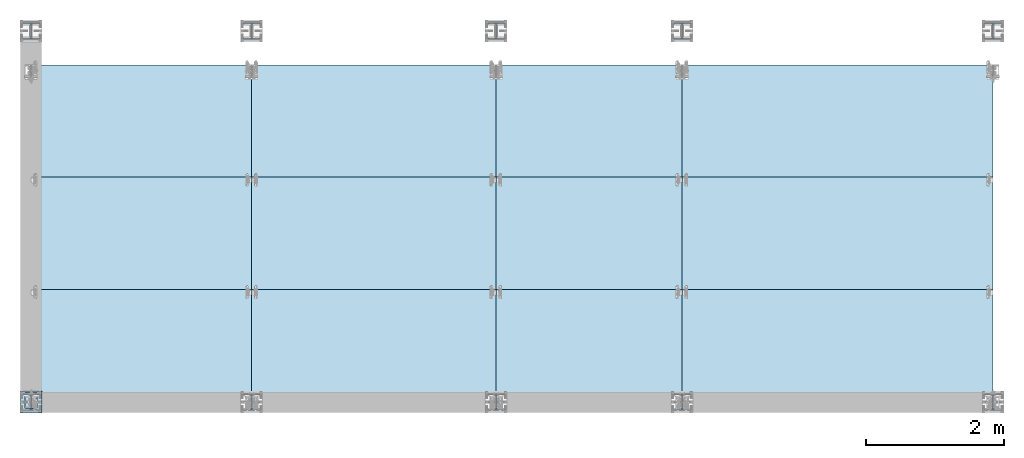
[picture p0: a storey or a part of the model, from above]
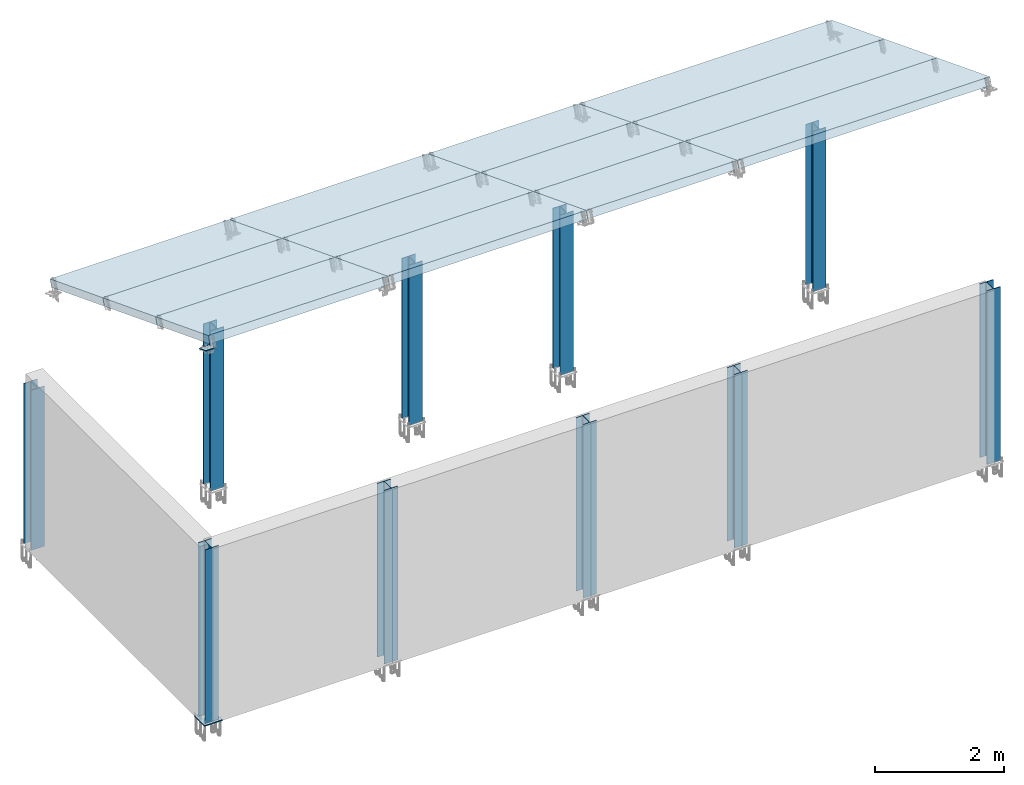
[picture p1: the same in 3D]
Properties of the parts of a building model (IFC4), part 1 of 2

# File
Description: ViewDefinition [CoordinationView]
Made in: IFC file generated by ModeSt (Tecnisoft s.a.s.)

# IfcBuildingStorey (2)
In: Uffici
Name | Elevation (m)
Storey 0 | 0
Storey 1 | 3.3

# IfcBeam: 2 HEB240 (25)
In: Storey 1
Type - PredefinedType: BEAM; Material: Acciaio
Description: 2 HEB240 - Acciaio
Pset_BeamCommon - LoadBearing: yes
BaseQuantities - ?: 0.01022 m2
Name | BaseQuantities, ? (m3) | BaseQuantities, ? (m)
108 | 0.0183619 | 1.79667
2 x 108 | 0.00918097 | 0.898333
108 | 0.0133541 | 1.30667
111 | 0.0183619 | 1.79667
2 x 111 | 0.00918097 | 0.898333
111 | 0.0133541 | 1.30667
110 | 0.0183619 | 1.79667
2 x 110 | 0.00918097 | 0.898333
110 | 0.0133541 | 1.30667
109 | 0.0183619 | 1.79667
2 x 109 | 0.00918097 | 0.898333
109 | 0.0133541 | 1.30667
112 | 0.0183619 | 1.79667
112 | 0.0050078 | 0.49
109 | 0.0050078 | 0.49
110 | 0.0050078 | 0.49
111 | 0.0050078 | 0.49
108 | 0.0050078 | 0.49
2 x 112 | 0.00918097 | 0.898333
112 | 0.0133541 | 1.30667

# IfcBeam: 3 IPE240 (16)
In: Storey 1
Type - PredefinedType: BEAM; Material: Acciaio
Description: 3 IPE240 - Acciaio
Pset_BeamCommon - LoadBearing: yes
BaseQuantities - ?: 0.00371848 m2
Name | BaseQuantities, ? (m3) | BaseQuantities, ? (m)
101 | 0.0100399 | 2.7
101 | 0.0132006 | 3.55
101 | 0.0119177 | 3.205
103 | 0.0100399 | 2.7
103 | 0.0132006 | 3.55
103 | 0.0119177 | 3.205
101 | 0.0167889 | 4.515
105 | 0.0100399 | 2.7
105 | 0.0132006 | 3.55
105 | 0.0119177 | 3.205
107 | 0.0100399 | 2.7
107 | 0.0132006 | 3.55
107 | 0.0119177 | 3.205
103 | 0.0167889 | 4.515
105 | 0.0167889 | 4.515
107 | 0.0167889 | 4.515

# IfcBeam: 5 IPE220 (20)
In: Storey 1
Type - PredefinedType: BEAM; Material: Acciaio
Description: 5 IPE220 - Acciaio
Pset_BeamCommon - LoadBearing: yes
BaseQuantities - ?: 0.00321344 m2
Name | BaseQuantities, ? (m3) | BaseQuantities, ? (m)
2 x 208 | 0.00281469 | 0.875912
2 x 209 | 0.00281469 | 0.875912
2 x 210 | 0.00281469 | 0.875912
2 x 212 | 0.00562938 | 1.75182
2 x 212 | 0.00281469 | 0.875912
2 x 211 | 0.00562938 | 1.75182
2 x 211 | 0.00281469 | 0.875912
2 x 210 | 0.00562938 | 1.75182
2 x 209 | 0.00562938 | 1.75182
2 x 208 | 0.00562938 | 1.75182

# IfcBeam: 6 IPE200 (16)
In: Storey 1
Type - PredefinedType: BEAM; Material: Acciaio
Description: 6 IPE200 - Acciaio
Pset_BeamCommon - LoadBearing: yes
BaseQuantities - ?: 0.0027248 m2
Name | BaseQuantities, ? (m3) | BaseQuantities, ? (m)
230 | 0.0123025 | 4.515
230 | 0.00735696 | 2.7
230 | 0.00967304 | 3.55
230 | 0.00873298 | 3.205
204 | 0.0123025 | 4.515
204 | 0.00735696 | 2.7
204 | 0.00967304 | 3.55
204 | 0.00873298 | 3.205
202 | 0.0123025 | 4.515
202 | 0.00735696 | 2.7
202 | 0.00967304 | 3.55
202 | 0.00873298 | 3.205
201 | 0.0123025 | 4.515
201 | 0.00735696 | 2.7
201 | 0.00967304 | 3.55
201 | 0.00873298 | 3.205

# IfcBuildingElementProxy: 4 Piatto50x5 (12)
In: Storey 1
Type - PredefinedType: MEMBER; Material: Acciaio controventi
Description: 4 Piatto50x5 - Acciaio
Pset_MemberCommon - LoadBearing: yes
BaseQuantities - ?: 0.00025 m2
Name | BaseQuantities, ? (m3) | BaseQuantities, ? (m)
2 x 0 | 0.00157189 | 6.28758
2 x 0 | 0.00123862 | 4.95447
2 x 0 | 0.00094979 | 3.79916
2 x 0 | 0.00132692 | 5.30769
2 x 0 | 0.00126973 | 5.07894
2 x 0 | 0.0014981 | 5.9924

# IfcColumn: 1 HEA240 (10)
In: Storey 0
Type - PredefinedType: COLUMN; Material: Acciaio
Description: 1 HEA240 - Acciaio
Pset_ColumnCommon - LoadBearing: yes
BaseQuantities - ?: 0.007305 m2; ?: 0.0241065 m3; ?: 3.3 m
Name
1
11
4
14
3
13
2
12
15
5

# IfcColumn: 7 HEA180 (10)
In: Storey 1
Type - PredefinedType: COLUMN; Material: Acciaio
Description: 7 HEA180 - Acciaio
Pset_ColumnCommon - LoadBearing: yes
BaseQuantities - ?: 0.004332 m2
Name | BaseQuantities, ? (m3) | BaseQuantities, ? (m)
10 | 0.00883728 | 2.04
9 | 0.00883728 | 2.04
8 | 0.00883728 | 2.04
7 | 0.00883728 | 2.04
6 | 0.00883728 | 2.04
5 | 0.0170681 | 3.94
4 | 0.0170681 | 3.94
3 | 0.0170681 | 3.94
2 | 0.0170681 | 3.94
1 | 0.0170681 | 3.94

# IfcFastener: Collegamenti -005_-004 -015_-014 0115_0114 (42)
In: Storey 1
Type - PredefinedType: WELD
Name | Description
36 x Collegamenti -005_-004 -015_-014 0115_0114 | 8x8
6 x Collegamenti -005_-004 -015_-014 0115_0114 | 15x15

# IfcFastener: Collegamenti 0001_0101 0002_0102 0003_0103 0004_0104 0005_0105 0011_0111 0012_0112 0013_0113 0014_0114 0015_0115 (160)
In: Storey 0
Type - PredefinedType: WELD
Description: 10x10

# IfcFastener: Collegamenti 0101_-001 0102_-002 0103_-003 0104_-004 (56)
In: Storey 1
Type - PredefinedType: WELD
Description: 14x14

# IfcFastener: Collegamenti 0101_0201 0102_0202 0103_0203 0104_0204 0105_0205 (120)
In: Storey 1
Type - PredefinedType: WELD
Name | Description
60 x Collegamenti 0101_0201 0102_0202 0103_0203 0104_0204 0105_0205 | 13x13
20 x Collegamenti 0101_0201 0102_0202 0103_0203 0104_0204 0105_0205 | 8x8
30 x Collegamenti 0101_0201 0102_0202 0103_0203 0104_0204 0105_0205 | 15x15
10 x Collegamenti 0101_0201 0102_0202 0103_0203 0104_0204 0105_0205 | 10x10

# IfcFastener: Collegamenti 0111_0011 0112_0012 0113_0013 0114_0014 0115_0015 (70)
In: Storey 1
Type - PredefinedType: WELD
Description: 10x10

# IfcFastener: Collegamento -001_-002 (14)
In: Storey 1
Type - PredefinedType: WELD
Name | Description
12 x Collegamento -001_-002 | 8x8
2 x Collegamento -001_-002 | 10x10

# IfcFastener: Collegamento -002_-001 (14)
In: Storey 1
Type - PredefinedType: WELD
Name | Description
12 x Collegamento -002_-001 | 8x8
2 x Collegamento -002_-001 | 10x10

# IfcFastener: Collegamento -002_-003 (14)
In: Storey 1
Type - PredefinedType: WELD
Name | Description
12 x Collegamento -002_-003 | 8x8
2 x Collegamento -002_-003 | 10x10

# IfcFastener: Collegamento -003_-002 (14)
In: Storey 1
Type - PredefinedType: WELD
Name | Description
12 x Collegamento -003_-002 | 8x8
2 x Collegamento -003_-002 | 10x10

# IfcFastener: Collegamento -003_-004 (14)
In: Storey 1
Type - PredefinedType: WELD
Name | Description
12 x Collegamento -003_-004 | 8x8
2 x Collegamento -003_-004 | 10x10

# IfcFastener: Collegamento -004_-003 (14)
In: Storey 1
Type - PredefinedType: WELD
Name | Description
12 x Collegamento -004_-003 | 8x8
2 x Collegamento -004_-003 | 10x10

# IfcFastener: Collegamento -004_-005 (14)
In: Storey 1
Type - PredefinedType: WELD
Name | Description
12 x Collegamento -004_-005 | 8x8
2 x Collegamento -004_-005 | 15x15

# IfcFastener: Collegamento -011_-012 (14)
In: Storey 1
Type - PredefinedType: WELD
Name | Description
12 x Collegamento -011_-012 | 8x8
2 x Collegamento -011_-012 | 10x10

# IfcFastener: Collegamento -012_-011 (14)
In: Storey 1
Type - PredefinedType: WELD
Name | Description
12 x Collegamento -012_-011 | 8x8
2 x Collegamento -012_-011 | 10x10

# IfcFastener: Collegamento -012_-013 (14)
In: Storey 1
Type - PredefinedType: WELD
Name | Description
12 x Collegamento -012_-013 | 8x8
2 x Collegamento -012_-013 | 10x10

# IfcFastener: Collegamento -013_-012 (14)
In: Storey 1
Type - PredefinedType: WELD
Name | Description
12 x Collegamento -013_-012 | 8x8
2 x Collegamento -013_-012 | 10x10

# IfcFastener: Collegamento -013_-014 (14)
In: Storey 1
Type - PredefinedType: WELD
Name | Description
12 x Collegamento -013_-014 | 8x8
2 x Collegamento -013_-014 | 10x10

# IfcFastener: Collegamento -014_-013 (14)
In: Storey 1
Type - PredefinedType: WELD
Name | Description
12 x Collegamento -014_-013 | 8x8
2 x Collegamento -014_-013 | 10x10

# IfcFastener: Collegamento -014_-015 (14)
In: Storey 1
Type - PredefinedType: WELD
Name | Description
12 x Collegamento -014_-015 | 8x8
2 x Collegamento -014_-015 | 15x15

# IfcFastener: Collegamento -016_-017 (16)
In: Storey 0
Type - PredefinedType: WELD
Name | Description
14 x Collegamento -016_-017 | 7x7
2 x Collegamento -016_-017 | 9x9

# IfcFastener: Collegamento -017_-016 (16)
In: Storey 0
Type - PredefinedType: WELD
Name | Description
14 x Collegamento -017_-016 | 7x7
2 x Collegamento -017_-016 | 9x9

# IfcFastener: Collegamento -017_-018 (16)
In: Storey 0
Type - PredefinedType: WELD
Name | Description
14 x Collegamento -017_-018 | 7x7
2 x Collegamento -017_-018 | 9x9

# IfcFastener: Collegamento -018_-017 (16)
In: Storey 0
Type - PredefinedType: WELD
Name | Description
14 x Collegamento -018_-017 | 7x7
2 x Collegamento -018_-017 | 9x9

# IfcFastener: Collegamento -018_-019 (16)
In: Storey 0
Type - PredefinedType: WELD
Name | Description
14 x Collegamento -018_-019 | 7x7
2 x Collegamento -018_-019 | 9x9

# IfcFastener: Collegamento -019_-018 (16)
In: Storey 0
Type - PredefinedType: WELD
Name | Description
14 x Collegamento -019_-018 | 7x7
2 x Collegamento -019_-018 | 9x9

# IfcFastener: Collegamento -019_-020 (16)
In: Storey 0
Type - PredefinedType: WELD
Name | Description
14 x Collegamento -019_-020 | 7x7
2 x Collegamento -019_-020 | 9x9

# IfcFastener: Collegamento -020_-019 (16)
In: Storey 0
Type - PredefinedType: WELD
Name | Description
14 x Collegamento -020_-019 | 7x7
2 x Collegamento -020_-019 | 9x9

# IfcFastener: Collegamento -026_-027 (16)
In: Storey 0
Type - PredefinedType: WELD
Name | Description
14 x Collegamento -026_-027 | 7x7
2 x Collegamento -026_-027 | 9x9

# IfcFastener: Collegamento -027_-026 (16)
In: Storey 0
Type - PredefinedType: WELD
Name | Description
14 x Collegamento -027_-026 | 7x7
2 x Collegamento -027_-026 | 9x9

# IfcFastener: Collegamento -027_-028 (16)
In: Storey 0
Type - PredefinedType: WELD
Name | Description
14 x Collegamento -027_-028 | 7x7
2 x Collegamento -027_-028 | 9x9

# IfcFastener: Collegamento -028_-027 (16)
In: Storey 0
Type - PredefinedType: WELD
Name | Description
14 x Collegamento -028_-027 | 7x7
2 x Collegamento -028_-027 | 9x9

# IfcFastener: Collegamento -028_-029 (16)
In: Storey 0
Type - PredefinedType: WELD
Name | Description
14 x Collegamento -028_-029 | 7x7
2 x Collegamento -028_-029 | 9x9

# IfcFastener: Collegamento -029_-028 (16)
In: Storey 0
Type - PredefinedType: WELD
Name | Description
14 x Collegamento -029_-028 | 7x7
2 x Collegamento -029_-028 | 9x9

# IfcFastener: Collegamento -029_-030 (16)
In: Storey 0
Type - PredefinedType: WELD
Name | Description
14 x Collegamento -029_-030 | 7x7
2 x Collegamento -029_-030 | 9x9

# IfcFastener: Collegamento -030_-029 (16)
In: Storey 0
Type - PredefinedType: WELD
Name | Description
14 x Collegamento -030_-029 | 7x7
2 x Collegamento -030_-029 | 9x9

# IfcFastener: Collegamento 0101_0202 (2)
In: Storey 1
Type - PredefinedType: WELD
Description: 7x7

# IfcFastener: Collegamento 0101_0206 (2)
In: Storey 1
Type - PredefinedType: WELD
Description: 7x7

# IfcFastener: Collegamento 0102_0201 (2)
In: Storey 1
Type - PredefinedType: WELD
Description: 7x7

# IfcFastener: Collegamento 0104_0205 (2)
In: Storey 1
Type - PredefinedType: WELD
Description: 7x7

# IfcFastener: Collegamento 0105_-005 (14)
In: Storey 1
Type - PredefinedType: WELD
Description: 14x14

# IfcFastener: Collegamento 0105_0204 (2)
In: Storey 1
Type - PredefinedType: WELD
Description: 7x7

# IfcFastener: Collegamento 0105_0210 (2)
In: Storey 1
Type - PredefinedType: WELD
Description: 7x7

# IfcFastener: Collegamento 0106_0201 (2)
In: Storey 1
Type - PredefinedType: WELD
Description: 7x7

# IfcFastener: Collegamento 0106_0206 (16)
In: Storey 1
Type - PredefinedType: WELD
Description: 8x8

# IfcFastener: Collegamento 0106_0207 (2)
In: Storey 1
Type - PredefinedType: WELD
Description: 7x7

# IfcFastener: Collegamento 0107_0206 (2)
In: Storey 1
Type - PredefinedType: WELD
Description: 7x7

# IfcFastener: Collegamento 0107_0207 (16)
In: Storey 1
Type - PredefinedType: WELD
Description: 8x8

# IfcFastener: Collegamento 0108_0208 (16)
In: Storey 1
Type - PredefinedType: WELD
Description: 8x8

# IfcFastener: Collegamento 0109_0209 (16)
In: Storey 1
Type - PredefinedType: WELD
Description: 8x8

# IfcFastener: Collegamento 0109_0210 (2)
In: Storey 1
Type - PredefinedType: WELD
Description: 7x7

# IfcFastener: Collegamento 0110_0205 (2)
In: Storey 1
Type - PredefinedType: WELD
Description: 7x7

# IfcFastener: Collegamento 0110_0209 (2)
In: Storey 1
Type - PredefinedType: WELD
Description: 7x7

# IfcFastener: Collegamento 0110_0210 (16)
In: Storey 1
Type - PredefinedType: WELD
Description: 8x8

# IfcFastener: Collegamento 0111_0112 (14)
In: Storey 1
Type - PredefinedType: WELD
Name | Description
12 x Collegamento 0111_0112 | 8x8
2 x Collegamento 0111_0112 | 10x10

# IfcFastener: Collegamento 0112_0111 (14)
In: Storey 1
Type - PredefinedType: WELD
Name | Description
12 x Collegamento 0112_0111 | 8x8
2 x Collegamento 0112_0111 | 10x10

# IfcFastener: Collegamento 0112_0113 (14)
In: Storey 1
Type - PredefinedType: WELD
Name | Description
12 x Collegamento 0112_0113 | 8x8
2 x Collegamento 0112_0113 | 10x10

# IfcFastener: Collegamento 0113_0112 (14)
In: Storey 1
Type - PredefinedType: WELD
Name | Description
12 x Collegamento 0113_0112 | 8x8
2 x Collegamento 0113_0112 | 10x10

# IfcFastener: Collegamento 0113_0114 (14)
In: Storey 1
Type - PredefinedType: WELD
Name | Description
12 x Collegamento 0113_0114 | 8x8
2 x Collegamento 0113_0114 | 10x10

# IfcFastener: Collegamento 0114_0113 (14)
In: Storey 1
Type - PredefinedType: WELD
Name | Description
12 x Collegamento 0114_0113 | 8x8
2 x Collegamento 0114_0113 | 10x10

# IfcFastener: Collegamento 0114_0115 (14)
In: Storey 1
Type - PredefinedType: WELD
Name | Description
12 x Collegamento 0114_0115 | 8x8
2 x Collegamento 0114_0115 | 10x10

# IfcFastener: Collegamento 0201_0101 (14)
In: Storey 0
Type - PredefinedType: WELD
Description: 8x8

# IfcFastener: Collegamento 0201_0102 (2)
In: Storey 0
Type - PredefinedType: WELD
Description: 7x7

# IfcFastener: Collegamento 0201_0106 (2)
In: Storey 0
Type - PredefinedType: WELD
Description: 7x7

# IfcFastener: Collegamento 0201_0202 (16)
In: Storey 0
Type - PredefinedType: WELD
Name | Description
14 x Collegamento 0201_0202 | 7x7
2 x Collegamento 0201_0202 | 9x9

# IfcFastener: Collegamento 0202_0101 (2)
In: Storey 0
Type - PredefinedType: WELD
Description: 7x7

# IfcFastener: Collegamento 0202_0102 (14)
In: Storey 0
Type - PredefinedType: WELD
Description: 8x8

# IfcFastener: Collegamento 0202_0201 (16)
In: Storey 0
Type - PredefinedType: WELD
Name | Description
14 x Collegamento 0202_0201 | 7x7
2 x Collegamento 0202_0201 | 9x9

# IfcFastener: Collegamento 0202_0203 (16)
In: Storey 0
Type - PredefinedType: WELD
Name | Description
14 x Collegamento 0202_0203 | 7x7
2 x Collegamento 0202_0203 | 9x9

# IfcFastener: Collegamento 0203_0103 (14)
In: Storey 0
Type - PredefinedType: WELD
Description: 8x8

# IfcFastener: Collegamento 0203_0202 (16)
In: Storey 0
Type - PredefinedType: WELD
Name | Description
14 x Collegamento 0203_0202 | 7x7
2 x Collegamento 0203_0202 | 9x9

# IfcFastener: Collegamento 0203_0204 (16)
In: Storey 0
Type - PredefinedType: WELD
Name | Description
14 x Collegamento 0203_0204 | 7x7
2 x Collegamento 0203_0204 | 9x9

# IfcFastener: Collegamento 0204_0104 (14)
In: Storey 0
Type - PredefinedType: WELD
Description: 8x8

# IfcFastener: Collegamento 0204_0105 (2)
In: Storey 0
Type - PredefinedType: WELD
Description: 7x7

# IfcFastener: Collegamento 0204_0203 (16)
In: Storey 0
Type - PredefinedType: WELD
Name | Description
14 x Collegamento 0204_0203 | 7x7
2 x Collegamento 0204_0203 | 9x9

# IfcFastener: Collegamento 0204_0205 (16)
In: Storey 0
Type - PredefinedType: WELD
Name | Description
14 x Collegamento 0204_0205 | 7x7
2 x Collegamento 0204_0205 | 9x9

# IfcFastener: Collegamento 0205_0104 (2)
In: Storey 0
Type - PredefinedType: WELD
Description: 7x7

# IfcFastener: Collegamento 0205_0105 (14)
In: Storey 0
Type - PredefinedType: WELD
Description: 8x8

# IfcFastener: Collegamento 0205_0110 (2)
In: Storey 0
Type - PredefinedType: WELD
Description: 7x7

# IfcFastener: Collegamento 0205_0204 (16)
In: Storey 0
Type - PredefinedType: WELD
Name | Description
14 x Collegamento 0205_0204 | 7x7
2 x Collegamento 0205_0204 | 9x9

# IfcFastener: Collegamento 0206_0101 (2)
In: Storey 0
Type - PredefinedType: WELD
Description: 7x7

# IfcFastener: Collegamento 0206_0106 (14)
In: Storey 0
Type - PredefinedType: WELD
Description: 8x8

# IfcFastener: Collegamento 0206_0107 (2)
In: Storey 0
Type - PredefinedType: WELD
Description: 7x7

# IfcFastener: Collegamento 0206_0207 (16)
In: Storey 0
Type - PredefinedType: WELD
Name | Description
14 x Collegamento 0206_0207 | 7x7
2 x Collegamento 0206_0207 | 9x9

# IfcFastener: Collegamento 0207_0106 (2)
In: Storey 0
Type - PredefinedType: WELD
Description: 7x7

# IfcFastener: Collegamento 0207_0107 (14)
In: Storey 0
Type - PredefinedType: WELD
Description: 8x8

# IfcFastener: Collegamento 0207_0206 (16)
In: Storey 0
Type - PredefinedType: WELD
Name | Description
14 x Collegamento 0207_0206 | 7x7
2 x Collegamento 0207_0206 | 9x9

# IfcFastener: Collegamento 0207_0208 (16)
In: Storey 0
Type - PredefinedType: WELD
Name | Description
14 x Collegamento 0207_0208 | 7x7
2 x Collegamento 0207_0208 | 9x9

# IfcFastener: Collegamento 0208_0108 (14)
In: Storey 0
Type - PredefinedType: WELD
Description: 8x8

# IfcFastener: Collegamento 0208_0207 (16)
In: Storey 0
Type - PredefinedType: WELD
Name | Description
14 x Collegamento 0208_0207 | 7x7
2 x Collegamento 0208_0207 | 9x9

# IfcFastener: Collegamento 0208_0209 (16)
In: Storey 0
Type - PredefinedType: WELD
Name | Description
14 x Collegamento 0208_0209 | 7x7
2 x Collegamento 0208_0209 | 9x9

# IfcFastener: Collegamento 0209_0109 (14)
In: Storey 0
Type - PredefinedType: WELD
Description: 8x8

# IfcFastener: Collegamento 0209_0110 (2)
In: Storey 0
Type - PredefinedType: WELD
Description: 7x7

# IfcFastener: Collegamento 0209_0208 (16)
In: Storey 0
Type - PredefinedType: WELD
Name | Description
14 x Collegamento 0209_0208 | 7x7
2 x Collegamento 0209_0208 | 9x9

# IfcFastener: Collegamento 0209_0210 (16)
In: Storey 0
Type - PredefinedType: WELD
Name | Description
14 x Collegamento 0209_0210 | 7x7
2 x Collegamento 0209_0210 | 9x9

# IfcFastener: Collegamento 0210_0105 (2)
In: Storey 0
Type - PredefinedType: WELD
Description: 7x7

# IfcFastener: Collegamento 0210_0109 (2)
In: Storey 0
Type - PredefinedType: WELD
Description: 7x7

# IfcFastener: Collegamento 0210_0110 (14)
In: Storey 0
Type - PredefinedType: WELD
Description: 8x8

# IfcFastener: Collegamento 0210_0209 (16)
In: Storey 0
Type - PredefinedType: WELD
Name | Description
14 x Collegamento 0210_0209 | 7x7
2 x Collegamento 0210_0209 | 9x9

# IfcMechanicalFastener: Collegamenti -005_-004 -015_-014 0115_0114 (48)
In: Storey 1
Type - PredefinedType: BOLT
Name | Description | NominalDiameter (m)
16 x Collegamenti -005_-004 -015_-014 0115_0114 | M12 | 0.0119999
12 x Collegamenti -005_-004 -015_-014 0115_0114 | M12 | 0.012
12 x Collegamenti -005_-004 -015_-014 0115_0114 | M24 | 0.024
8 x Collegamenti -005_-004 -015_-014 0115_0114 | M12 | 0.0119997

# IfcMechanicalFastener: Collegamenti 0001_0101 0002_0102 0003_0103 0004_0104 0005_0105 0011_0111 0012_0112 0013_0113 0014_0114 0015_0115 (300)
In: Storey 0
Type - PredefinedType: BOLT
Name | Description | NominalDiameter (m)
36 x Collegamenti 0001_0101 0002_0102 0003_0103 0004_0104 0005_0105 0011_0111 0012_0112 0013_0113 0014_0114 0015_0115 | M12 | 0.012
120 x Collegamenti 0001_0101 0002_0102 0003_0103 0004_0104 0005_0105 0011_0111 0012_0112 0013_0113 0014_0114 0015_0115 | M24 | 0.024
36 x Collegamenti 0001_0101 0002_0102 0003_0103 0004_0104 0005_0105 0011_0111 0012_0112 0013_0113 0014_0114 0015_0115 | M12 | 0.0119996
36 x Collegamenti 0001_0101 0002_0102 0003_0103 0004_0104 0005_0105 0011_0111 0012_0112 0013_0113 0014_0114 0015_0115 | M12 | 0.0119998
36 x Collegamenti 0001_0101 0002_0102 0003_0103 0004_0104 0005_0105 0011_0111 0012_0112 0013_0113 0014_0114 0015_0115 | M12 | 0.0119999
36 x Collegamenti 0001_0101 0002_0102 0003_0103 0004_0104 0005_0105 0011_0111 0012_0112 0013_0113 0014_0114 0015_0115 | M12 | 0.0119997

# IfcMechanicalFastener: Collegamenti 0101_-001 0102_-002 0103_-003 0104_-004 (96)
In: Storey 1
Type - PredefinedType: BOLT
Name | Description | NominalDiameter (m)
12 x Collegamenti 0101_-001 0102_-002 0103_-003 0104_-004 | M12 | 0.0119999
24 x Collegamenti 0101_-001 0102_-002 0103_-003 0104_-004 | M12 | 0.012
24 x Collegamenti 0101_-001 0102_-002 0103_-003 0104_-004 | M24 | 0.024
12 x Collegamenti 0101_-001 0102_-002 0103_-003 0104_-004 | M12 | 0.0119998
24 x Collegamenti 0101_-001 0102_-002 0103_-003 0104_-004 | M12 | 0.0119997

# IfcMechanicalFastener: Collegamenti 0101_0201 0102_0202 0103_0203 0104_0204 0105_0205 (80)
In: Storey 1
Type - PredefinedType: BOLT
Name | Description | NominalDiameter (m)
36 x Collegamenti 0101_0201 0102_0202 0103_0203 0104_0204 0105_0205 | M12 | 0.012
20 x Collegamenti 0101_0201 0102_0202 0103_0203 0104_0204 0105_0205 | M24 | 0.024
24 x Collegamenti 0101_0201 0102_0202 0103_0203 0104_0204 0105_0205 | M12 | 0.0119998

# IfcMechanicalFastener: Collegamenti 0111_0011 0112_0012 0113_0013 0114_0014 0115_0015 (160)
In: Storey 1
Type - PredefinedType: BOLT
Name | Description | NominalDiameter (m)
32 x Collegamenti 0111_0011 0112_0012 0113_0013 0114_0014 0115_0015 | M12 | 0.0119999
40 x Collegamenti 0111_0011 0112_0012 0113_0013 0114_0014 0115_0015 | M12 | 0.012
40 x Collegamenti 0111_0011 0112_0012 0113_0013 0114_0014 0115_0015 | M24 | 0.024
16 x Collegamenti 0111_0011 0112_0012 0113_0013 0114_0014 0115_0015 | M12 | 0.0119996
32 x Collegamenti 0111_0011 0112_0012 0113_0013 0114_0014 0115_0015 | M12 | 0.0119997

# IfcMechanicalFastener: Collegamento -001_-002 (16)
In: Storey 1
Type - PredefinedType: BOLT
Name | Description | NominalDiameter (m)
8 x Collegamento -001_-002 | M12 | 0.0119999
4 x Collegamento -001_-002 | M12 | 0.012
4 x Collegamento -001_-002 | M24 | 0.024

# IfcMechanicalFastener: Collegamento -002_-001 (16)
In: Storey 1
Type - PredefinedType: BOLT
Name | Description | NominalDiameter (m)
8 x Collegamento -002_-001 | M12 | 0.0119999
4 x Collegamento -002_-001 | M12 | 0.012
4 x Collegamento -002_-001 | M24 | 0.024

# IfcMechanicalFastener: Collegamento -002_-003 (16)
In: Storey 1
Type - PredefinedType: BOLT
Name | Description | NominalDiameter (m)
8 x Collegamento -002_-003 | M12 | 0.0119999
4 x Collegamento -002_-003 | M12 | 0.012
4 x Collegamento -002_-003 | M24 | 0.024

# IfcMechanicalFastener: Collegamento -003_-002 (16)
In: Storey 1
Type - PredefinedType: BOLT
Name | Description | NominalDiameter (m)
8 x Collegamento -003_-002 | M12 | 0.0119999
4 x Collegamento -003_-002 | M12 | 0.012
4 x Collegamento -003_-002 | M24 | 0.024

# IfcMechanicalFastener: Collegamento -003_-004 (16)
In: Storey 1
Type - PredefinedType: BOLT
Name | Description | NominalDiameter (m)
8 x Collegamento -003_-004 | M12 | 0.0119999
4 x Collegamento -003_-004 | M12 | 0.012
4 x Collegamento -003_-004 | M24 | 0.024

# IfcMechanicalFastener: Collegamento -004_-003 (16)
In: Storey 1
Type - PredefinedType: BOLT
Name | Description | NominalDiameter (m)
8 x Collegamento -004_-003 | M12 | 0.0119999
4 x Collegamento -004_-003 | M12 | 0.012
4 x Collegamento -004_-003 | M24 | 0.024

# IfcMechanicalFastener: Collegamento -004_-005 (16)
In: Storey 1
Type - PredefinedType: BOLT
Name | Description | NominalDiameter (m)
8 x Collegamento -004_-005 | M12 | 0.0119999
4 x Collegamento -004_-005 | M12 | 0.012
4 x Collegamento -004_-005 | M24 | 0.024

# IfcMechanicalFastener: Collegamento -011_-012 (16)
In: Storey 1
Type - PredefinedType: BOLT
Name | Description | NominalDiameter (m)
8 x Collegamento -011_-012 | M12 | 0.0119999
4 x Collegamento -011_-012 | M12 | 0.012
4 x Collegamento -011_-012 | M24 | 0.024

# IfcMechanicalFastener: Collegamento -012_-011 (16)
In: Storey 1
Type - PredefinedType: BOLT
Name | Description | NominalDiameter (m)
8 x Collegamento -012_-011 | M12 | 0.0119999
4 x Collegamento -012_-011 | M12 | 0.012
4 x Collegamento -012_-011 | M24 | 0.024

# IfcMechanicalFastener: Collegamento -012_-013 (16)
In: Storey 1
Type - PredefinedType: BOLT
Name | Description | NominalDiameter (m)
8 x Collegamento -012_-013 | M12 | 0.0119999
4 x Collegamento -012_-013 | M12 | 0.012
4 x Collegamento -012_-013 | M24 | 0.024

# IfcMechanicalFastener: Collegamento -013_-012 (16)
In: Storey 1
Type - PredefinedType: BOLT
Name | Description | NominalDiameter (m)
8 x Collegamento -013_-012 | M12 | 0.0119999
4 x Collegamento -013_-012 | M12 | 0.012
4 x Collegamento -013_-012 | M24 | 0.024

# IfcMechanicalFastener: Collegamento -013_-014 (16)
In: Storey 1
Type - PredefinedType: BOLT
Name | Description | NominalDiameter (m)
8 x Collegamento -013_-014 | M12 | 0.0119999
4 x Collegamento -013_-014 | M12 | 0.012
4 x Collegamento -013_-014 | M24 | 0.024

# IfcMechanicalFastener: Collegamento -014_-013 (16)
In: Storey 1
Type - PredefinedType: BOLT
Name | Description | NominalDiameter (m)
8 x Collegamento -014_-013 | M12 | 0.0119999
4 x Collegamento -014_-013 | M12 | 0.012
4 x Collegamento -014_-013 | M24 | 0.024

# IfcMechanicalFastener: Collegamento -014_-015 (16)
In: Storey 1
Type - PredefinedType: BOLT
Name | Description | NominalDiameter (m)
8 x Collegamento -014_-015 | M12 | 0.0119999
4 x Collegamento -014_-015 | M12 | 0.012
4 x Collegamento -014_-015 | M24 | 0.024

# IfcMechanicalFastener: Collegamento -016_-017 (16)
In: Storey 0
Type - PredefinedType: BOLT
Name | Description | NominalDiameter (m)
4 x Collegamento -016_-017 | M12 | 0.0119997
4 x Collegamento -016_-017 | M12 | 0.012
4 x Collegamento -016_-017 | M24 | 0.024
4 x Collegamento -016_-017 | M12 | 0.0119999

# IfcMechanicalFastener: Collegamento -017_-016 (16)
In: Storey 0
Type - PredefinedType: BOLT
Name | Description | NominalDiameter (m)
4 x Collegamento -017_-016 | M12 | 0.0119999
4 x Collegamento -017_-016 | M12 | 0.012
4 x Collegamento -017_-016 | M24 | 0.024
4 x Collegamento -017_-016 | M12 | 0.0119997

# IfcMechanicalFastener: Collegamento -017_-018 (16)
In: Storey 0
Type - PredefinedType: BOLT
Name | Description | NominalDiameter (m)
4 x Collegamento -017_-018 | M12 | 0.0119997
4 x Collegamento -017_-018 | M12 | 0.012
4 x Collegamento -017_-018 | M24 | 0.024
4 x Collegamento -017_-018 | M12 | 0.0119999

# IfcMechanicalFastener: Collegamento -018_-017 (16)
In: Storey 0
Type - PredefinedType: BOLT
Name | Description | NominalDiameter (m)
4 x Collegamento -018_-017 | M12 | 0.0119999
4 x Collegamento -018_-017 | M12 | 0.012
4 x Collegamento -018_-017 | M24 | 0.024
4 x Collegamento -018_-017 | M12 | 0.0119997

# IfcMechanicalFastener: Collegamento -018_-019 (16)
In: Storey 0
Type - PredefinedType: BOLT
Name | Description | NominalDiameter (m)
4 x Collegamento -018_-019 | M12 | 0.0119997
4 x Collegamento -018_-019 | M12 | 0.012
4 x Collegamento -018_-019 | M24 | 0.024
4 x Collegamento -018_-019 | M12 | 0.0119999

# IfcMechanicalFastener: Collegamento -019_-018 (16)
In: Storey 0
Type - PredefinedType: BOLT
Name | Description | NominalDiameter (m)
4 x Collegamento -019_-018 | M12 | 0.0119999
4 x Collegamento -019_-018 | M12 | 0.012
4 x Collegamento -019_-018 | M24 | 0.024
4 x Collegamento -019_-018 | M12 | 0.0119997

# IfcMechanicalFastener: Collegamento -019_-020 (16)
In: Storey 0
Type - PredefinedType: BOLT
Name | Description | NominalDiameter (m)
4 x Collegamento -019_-020 | M12 | 0.0119997
4 x Collegamento -019_-020 | M12 | 0.012
4 x Collegamento -019_-020 | M24 | 0.024
4 x Collegamento -019_-020 | M12 | 0.0119999

# IfcMechanicalFastener: Collegamento -020_-019 (16)
In: Storey 0
Type - PredefinedType: BOLT
Name | Description | NominalDiameter (m)
4 x Collegamento -020_-019 | M12 | 0.0119999
4 x Collegamento -020_-019 | M12 | 0.012
4 x Collegamento -020_-019 | M24 | 0.024
4 x Collegamento -020_-019 | M12 | 0.0119997

# IfcMechanicalFastener: Collegamento -026_-027 (16)
In: Storey 0
Type - PredefinedType: BOLT
Name | Description | NominalDiameter (m)
4 x Collegamento -026_-027 | M12 | 0.0119999
4 x Collegamento -026_-027 | M12 | 0.012
4 x Collegamento -026_-027 | M24 | 0.024
4 x Collegamento -026_-027 | M12 | 0.0119998

# IfcMechanicalFastener: Collegamento -027_-026 (16)
In: Storey 0
Type - PredefinedType: BOLT
Name | Description | NominalDiameter (m)
4 x Collegamento -027_-026 | M12 | 0.0119998
4 x Collegamento -027_-026 | M12 | 0.012
4 x Collegamento -027_-026 | M24 | 0.024
4 x Collegamento -027_-026 | M12 | 0.0119999

# IfcMechanicalFastener: Collegamento -027_-028 (16)
In: Storey 0
Type - PredefinedType: BOLT
Name | Description | NominalDiameter (m)
4 x Collegamento -027_-028 | M12 | 0.0119999
4 x Collegamento -027_-028 | M12 | 0.012
4 x Collegamento -027_-028 | M24 | 0.024
4 x Collegamento -027_-028 | M12 | 0.0119998

# IfcMechanicalFastener: Collegamento -028_-027 (16)
In: Storey 0
Type - PredefinedType: BOLT
Name | Description | NominalDiameter (m)
4 x Collegamento -028_-027 | M12 | 0.0119998
4 x Collegamento -028_-027 | M12 | 0.012
4 x Collegamento -028_-027 | M24 | 0.024
4 x Collegamento -028_-027 | M12 | 0.0119999

# IfcMechanicalFastener: Collegamento -028_-029 (16)
In: Storey 0
Type - PredefinedType: BOLT
Name | Description | NominalDiameter (m)
4 x Collegamento -028_-029 | M12 | 0.0119999
4 x Collegamento -028_-029 | M12 | 0.012
4 x Collegamento -028_-029 | M24 | 0.024
4 x Collegamento -028_-029 | M12 | 0.0119998

# IfcMechanicalFastener: Collegamento -029_-028 (16)
In: Storey 0
Type - PredefinedType: BOLT
Name | Description | NominalDiameter (m)
4 x Collegamento -029_-028 | M12 | 0.0119998
4 x Collegamento -029_-028 | M12 | 0.012
4 x Collegamento -029_-028 | M24 | 0.024
4 x Collegamento -029_-028 | M12 | 0.0119999

# IfcMechanicalFastener: Collegamento -029_-030 (16)
In: Storey 0
Type - PredefinedType: BOLT
Name | Description | NominalDiameter (m)
4 x Collegamento -029_-030 | M12 | 0.0119999
4 x Collegamento -029_-030 | M12 | 0.012
4 x Collegamento -029_-030 | M24 | 0.024
4 x Collegamento -029_-030 | M12 | 0.0119998

# IfcMechanicalFastener: Collegamento -030_-029 (16)
In: Storey 0
Type - PredefinedType: BOLT
Name | Description | NominalDiameter (m)
4 x Collegamento -030_-029 | M12 | 0.0119998
4 x Collegamento -030_-029 | M12 | 0.012
4 x Collegamento -030_-029 | M24 | 0.024
4 x Collegamento -030_-029 | M12 | 0.0119999

# IfcMechanicalFastener: Collegamento 0101_0202 (8)
In: Storey 1
Type - PredefinedType: BOLT
Name | Description | NominalDiameter (m)
6 x Collegamento 0101_0202 | M12 | 0.012
2 x Collegamento 0101_0202 | M24 | 0.024

# IfcMechanicalFastener: Collegamento 0101_0206 (8)
In: Storey 1
Type - PredefinedType: BOLT
Name | Description | NominalDiameter (m)
4 x Collegamento 0101_0206 | M12 | 0.0119998
2 x Collegamento 0101_0206 | M12 | 0.012
2 x Collegamento 0101_0206 | M24 | 0.024

# IfcMechanicalFastener: Collegamento 0102_0201 (8)
In: Storey 1
Type - PredefinedType: BOLT
Name | Description | NominalDiameter (m)
4 x Collegamento 0102_0201 | M12 | 0.0119999
2 x Collegamento 0102_0201 | M12 | 0.012
2 x Collegamento 0102_0201 | M24 | 0.024

# IfcMechanicalFastener: Collegamento 0104_0205 (8)
In: Storey 1
Type - PredefinedType: BOLT
Name | Description | NominalDiameter (m)
4 x Collegamento 0104_0205 | M12 | 0.0119995
2 x Collegamento 0104_0205 | M12 | 0.012
2 x Collegamento 0104_0205 | M24 | 0.024

# IfcMechanicalFastener: Collegamento 0105_-005 (24)
In: Storey 1
Type - PredefinedType: BOLT
Name | Description | NominalDiameter (m)
12 x Collegamento 0105_-005 | M12 | 0.0119997
6 x Collegamento 0105_-005 | M12 | 0.012
6 x Collegamento 0105_-005 | M24 | 0.024

# IfcMechanicalFastener: Collegamento 0105_0204 (8)
In: Storey 1
Type - PredefinedType: BOLT
Name | Description | NominalDiameter (m)
2 x Collegamento 0105_0204 | M12 | 0.0119999
4 x Collegamento 0105_0204 | M12 | 0.012
2 x Collegamento 0105_0204 | M24 | 0.024

# IfcMechanicalFastener: Collegamento 0105_0210 (8)
In: Storey 1
Type - PredefinedType: BOLT
Name | Description | NominalDiameter (m)
4 x Collegamento 0105_0210 | M12 | 0.0119998
2 x Collegamento 0105_0210 | M12 | 0.012
2 x Collegamento 0105_0210 | M24 | 0.024

# IfcMechanicalFastener: Collegamento 0106_0201 (8)
In: Storey 1
Type - PredefinedType: BOLT
Name | Description | NominalDiameter (m)
4 x Collegamento 0106_0201 | M12 | 0.0119999
2 x Collegamento 0106_0201 | M12 | 0.012
2 x Collegamento 0106_0201 | M24 | 0.024

# IfcMechanicalFastener: Collegamento 0106_0206 (32)
In: Storey 1
Type - PredefinedType: BOLT
Name | Description | NominalDiameter (m)
16 x Collegamento 0106_0206 | M12 | 0.0119999
8 x Collegamento 0106_0206 | M12 | 0.012
8 x Collegamento 0106_0206 | M24 | 0.024

# IfcMechanicalFastener: Collegamento 0106_0207 (8)
In: Storey 1
Type - PredefinedType: BOLT
Name | Description | NominalDiameter (m)
4 x Collegamento 0106_0207 | M12 | 0.012
2 x Collegamento 0106_0207 | M24 | 0.024
2 x Collegamento 0106_0207 | M12 | 0.0119999

# IfcMechanicalFastener: Collegamento 0107_0206 (8)
In: Storey 1
Type - PredefinedType: BOLT
Name | Description | NominalDiameter (m)
4 x Collegamento 0107_0206 | M12 | 0.0119999
2 x Collegamento 0107_0206 | M12 | 0.012
2 x Collegamento 0107_0206 | M24 | 0.024

# IfcMechanicalFastener: Collegamento 0107_0207 (32)
In: Storey 1
Type - PredefinedType: BOLT
Name | Description | NominalDiameter (m)
16 x Collegamento 0107_0207 | M12 | 0.0119998
8 x Collegamento 0107_0207 | M12 | 0.012
8 x Collegamento 0107_0207 | M24 | 0.024

# IfcMechanicalFastener: Collegamento 0108_0208 (32)
In: Storey 1
Type - PredefinedType: BOLT
Name | Description | NominalDiameter (m)
16 x Collegamento 0108_0208 | M12 | 0.0119997
8 x Collegamento 0108_0208 | M12 | 0.012
8 x Collegamento 0108_0208 | M24 | 0.024

# IfcMechanicalFastener: Collegamento 0109_0209 (32)
In: Storey 1
Type - PredefinedType: BOLT
Name | Description | NominalDiameter (m)
16 x Collegamento 0109_0209 | M12 | 0.0119997
8 x Collegamento 0109_0209 | M12 | 0.012
8 x Collegamento 0109_0209 | M24 | 0.024

# IfcMechanicalFastener: Collegamento 0109_0210 (8)
In: Storey 1
Type - PredefinedType: BOLT
Name | Description | NominalDiameter (m)
4 x Collegamento 0109_0210 | M12 | 0.0119999
2 x Collegamento 0109_0210 | M12 | 0.012
2 x Collegamento 0109_0210 | M24 | 0.024

# IfcMechanicalFastener: Collegamento 0110_0205 (8)
In: Storey 1
Type - PredefinedType: BOLT
Name | Description | NominalDiameter (m)
4 x Collegamento 0110_0205 | M12 | 0.0119998
2 x Collegamento 0110_0205 | M12 | 0.012
2 x Collegamento 0110_0205 | M24 | 0.024

# IfcMechanicalFastener: Collegamento 0110_0209 (8)
In: Storey 1
Type - PredefinedType: BOLT
Name | Description | NominalDiameter (m)
4 x Collegamento 0110_0209 | M12 | 0.0119999
2 x Collegamento 0110_0209 | M12 | 0.012
2 x Collegamento 0110_0209 | M24 | 0.024

# IfcMechanicalFastener: Collegamento 0110_0210 (32)
In: Storey 1
Type - PredefinedType: BOLT
Name | Description | NominalDiameter (m)
16 x Collegamento 0110_0210 | M12 | 0.0119997
8 x Collegamento 0110_0210 | M12 | 0.012
8 x Collegamento 0110_0210 | M24 | 0.024

# IfcMechanicalFastener: Collegamento 0111_0112 (16)
In: Storey 1
Type - PredefinedType: BOLT
Name | Description | NominalDiameter (m)
8 x Collegamento 0111_0112 | M12 | 0.0119996
4 x Collegamento 0111_0112 | M12 | 0.012
4 x Collegamento 0111_0112 | M24 | 0.024

# IfcMechanicalFastener: Collegamento 0112_0111 (16)
In: Storey 1
Type - PredefinedType: BOLT
Name | Description | NominalDiameter (m)
8 x Collegamento 0112_0111 | M12 | 0.0119996
4 x Collegamento 0112_0111 | M12 | 0.012
4 x Collegamento 0112_0111 | M24 | 0.024

# IfcMechanicalFastener: Collegamento 0112_0113 (16)
In: Storey 1
Type - PredefinedType: BOLT
Name | Description | NominalDiameter (m)
8 x Collegamento 0112_0113 | M12 | 0.0119996
4 x Collegamento 0112_0113 | M12 | 0.012
4 x Collegamento 0112_0113 | M24 | 0.024

# IfcMechanicalFastener: Collegamento 0113_0112 (16)
In: Storey 1
Type - PredefinedType: BOLT
Name | Description | NominalDiameter (m)
8 x Collegamento 0113_0112 | M12 | 0.0119996
4 x Collegamento 0113_0112 | M12 | 0.012
4 x Collegamento 0113_0112 | M24 | 0.024

# IfcMechanicalFastener: Collegamento 0113_0114 (16)
In: Storey 1
Type - PredefinedType: BOLT
Name | Description | NominalDiameter (m)
8 x Collegamento 0113_0114 | M12 | 0.0119996
4 x Collegamento 0113_0114 | M12 | 0.012
4 x Collegamento 0113_0114 | M24 | 0.024

# IfcMechanicalFastener: Collegamento 0114_0113 (16)
In: Storey 1
Type - PredefinedType: BOLT
Name | Description | NominalDiameter (m)
8 x Collegamento 0114_0113 | M12 | 0.0119996
4 x Collegamento 0114_0113 | M12 | 0.012
4 x Collegamento 0114_0113 | M24 | 0.024

# IfcMechanicalFastener: Collegamento 0114_0115 (16)
In: Storey 1
Type - PredefinedType: BOLT
Name | Description | NominalDiameter (m)
8 x Collegamento 0114_0115 | M12 | 0.0119996
4 x Collegamento 0114_0115 | M12 | 0.012
4 x Collegamento 0114_0115 | M24 | 0.024

# IfcMechanicalFastener: Collegamento 0201_0101 (24)
In: Storey 0
Type - PredefinedType: BOLT
Name | Description | NominalDiameter (m)
18 x Collegamento 0201_0101 | M12 | 0.012
6 x Collegamento 0201_0101 | M24 | 0.024

# IfcMechanicalFastener: Collegamento 0201_0102 (8)
In: Storey 0
Type - PredefinedType: BOLT
Name | Description | NominalDiameter (m)
4 x Collegamento 0201_0102 | M12 | 0.0119998
2 x Collegamento 0201_0102 | M12 | 0.012
2 x Collegamento 0201_0102 | M24 | 0.024

# IfcMechanicalFastener: Collegamento 0201_0106 (8)
In: Storey 0
Type - PredefinedType: BOLT
Name | Description | NominalDiameter (m)
2 x Collegamento 0201_0106 | M12 | 0.0119997
4 x Collegamento 0201_0106 | M12 | 0.012
2 x Collegamento 0201_0106 | M24 | 0.024

# IfcMechanicalFastener: Collegamento 0201_0202 (16)
In: Storey 0
Type - PredefinedType: BOLT
Name | Description | NominalDiameter (m)
8 x Collegamento 0201_0202 | M12 | 0.0119999
4 x Collegamento 0201_0202 | M12 | 0.012
4 x Collegamento 0201_0202 | M24 | 0.024

# IfcMechanicalFastener: Collegamento 0202_0101 (8)
In: Storey 0
Type - PredefinedType: BOLT
Name | Description | NominalDiameter (m)
2 x Collegamento 0202_0101 | M12 | 0.0119998
2 x Collegamento 0202_0101 | M12 | 0.012
2 x Collegamento 0202_0101 | M24 | 0.024
2 x Collegamento 0202_0101 | M12 | 0.0119999

# IfcMechanicalFastener: Collegamento 0202_0102 (24)
In: Storey 0
Type - PredefinedType: BOLT
Name | Description | NominalDiameter (m)
18 x Collegamento 0202_0102 | M12 | 0.012
6 x Collegamento 0202_0102 | M24 | 0.024

# IfcMechanicalFastener: Collegamento 0202_0201 (16)
In: Storey 0
Type - PredefinedType: BOLT
Name | Description | NominalDiameter (m)
8 x Collegamento 0202_0201 | M12 | 0.0119999
4 x Collegamento 0202_0201 | M12 | 0.012
4 x Collegamento 0202_0201 | M24 | 0.024

# IfcMechanicalFastener: Collegamento 0202_0203 (16)
In: Storey 0
Type - PredefinedType: BOLT
Name | Description | NominalDiameter (m)
8 x Collegamento 0202_0203 | M12 | 0.0119999
4 x Collegamento 0202_0203 | M12 | 0.012
4 x Collegamento 0202_0203 | M24 | 0.024

# IfcMechanicalFastener: Collegamento 0203_0103 (24)
In: Storey 0
Type - PredefinedType: BOLT
Name | Description | NominalDiameter (m)
12 x Collegamento 0203_0103 | M12 | 0.0119996
6 x Collegamento 0203_0103 | M12 | 0.012
6 x Collegamento 0203_0103 | M24 | 0.024

# IfcMechanicalFastener: Collegamento 0203_0202 (16)
In: Storey 0
Type - PredefinedType: BOLT
Name | Description | NominalDiameter (m)
8 x Collegamento 0203_0202 | M12 | 0.0119999
4 x Collegamento 0203_0202 | M12 | 0.012
4 x Collegamento 0203_0202 | M24 | 0.024

# IfcMechanicalFastener: Collegamento 0203_0204 (16)
In: Storey 0
Type - PredefinedType: BOLT
Name | Description | NominalDiameter (m)
8 x Collegamento 0203_0204 | M12 | 0.0119999
4 x Collegamento 0203_0204 | M12 | 0.012
4 x Collegamento 0203_0204 | M24 | 0.024

# IfcMechanicalFastener: Collegamento 0204_0104 (24)
In: Storey 0
Type - PredefinedType: BOLT
Name | Description | NominalDiameter (m)
10 x Collegamento 0204_0104 | M12 | 0.0119997
6 x Collegamento 0204_0104 | M12 | 0.012
6 x Collegamento 0204_0104 | M24 | 0.024
2 x Collegamento 0204_0104 | M12 | 0.0119998

# IfcMechanicalFastener: Collegamento 0204_0105 (8)
In: Storey 0
Type - PredefinedType: BOLT
Name | Description | NominalDiameter (m)
2 x Collegamento 0204_0105 | M12 | 0.0119996
2 x Collegamento 0204_0105 | M12 | 0.012
2 x Collegamento 0204_0105 | M24 | 0.024
2 x Collegamento 0204_0105 | M12 | 0.0119994

# IfcMechanicalFastener: Collegamento 0204_0203 (16)
In: Storey 0
Type - PredefinedType: BOLT
Name | Description | NominalDiameter (m)
8 x Collegamento 0204_0203 | M12 | 0.0119999
4 x Collegamento 0204_0203 | M12 | 0.012
4 x Collegamento 0204_0203 | M24 | 0.024

# IfcMechanicalFastener: Collegamento 0204_0205 (16)
In: Storey 0
Type - PredefinedType: BOLT
Name | Description | NominalDiameter (m)
8 x Collegamento 0204_0205 | M12 | 0.0119999
4 x Collegamento 0204_0205 | M12 | 0.012
4 x Collegamento 0204_0205 | M24 | 0.024

# IfcMechanicalFastener: Collegamento 0205_0104 (8)
In: Storey 0
Type - PredefinedType: BOLT
Name | Description | NominalDiameter (m)
2 x Collegamento 0205_0104 | M12 | 0.0119994
2 x Collegamento 0205_0104 | M12 | 0.012
2 x Collegamento 0205_0104 | M24 | 0.024
2 x Collegamento 0205_0104 | M12 | 0.0119998

# IfcMechanicalFastener: Collegamento 0205_0105 (24)
In: Storey 0
Type - PredefinedType: BOLT
Name | Description | NominalDiameter (m)
10 x Collegamento 0205_0105 | M12 | 0.0119997
6 x Collegamento 0205_0105 | M12 | 0.012
6 x Collegamento 0205_0105 | M24 | 0.024
2 x Collegamento 0205_0105 | M12 | 0.0119998

# IfcMechanicalFastener: Collegamento 0205_0110 (8)
In: Storey 0
Type - PredefinedType: BOLT
Name | Description | NominalDiameter (m)
4 x Collegamento 0205_0110 | M12 | 0.0119999
2 x Collegamento 0205_0110 | M12 | 0.012
2 x Collegamento 0205_0110 | M24 | 0.024

# IfcMechanicalFastener: Collegamento 0205_0204 (16)
In: Storey 0
Type - PredefinedType: BOLT
Name | Description | NominalDiameter (m)
8 x Collegamento 0205_0204 | M12 | 0.0119999
4 x Collegamento 0205_0204 | M12 | 0.012
4 x Collegamento 0205_0204 | M24 | 0.024

# IfcMechanicalFastener: Collegamento 0206_0101 (8)
In: Storey 0
Type - PredefinedType: BOLT
Name | Description | NominalDiameter (m)
4 x Collegamento 0206_0101 | M12 | 0.0119996
2 x Collegamento 0206_0101 | M12 | 0.012
2 x Collegamento 0206_0101 | M24 | 0.024

# IfcMechanicalFastener: Collegamento 0206_0106 (24)
In: Storey 0
Type - PredefinedType: BOLT
Name | Description | NominalDiameter (m)
10 x Collegamento 0206_0106 | M12 | 0.0119999
8 x Collegamento 0206_0106 | M12 | 0.012
6 x Collegamento 0206_0106 | M24 | 0.024

# IfcMechanicalFastener: Collegamento 0206_0107 (8)
In: Storey 0
Type - PredefinedType: BOLT
Name | Description | NominalDiameter (m)
4 x Collegamento 0206_0107 | M12 | 0.012
2 x Collegamento 0206_0107 | M24 | 0.024
2 x Collegamento 0206_0107 | M12 | 0.0119996

# IfcMechanicalFastener: Collegamento 0206_0207 (16)
In: Storey 0
Type - PredefinedType: BOLT
Name | Description | NominalDiameter (m)
8 x Collegamento 0206_0207 | M12 | 0.0119998
4 x Collegamento 0206_0207 | M12 | 0.012
4 x Collegamento 0206_0207 | M24 | 0.024

# IfcMechanicalFastener: Collegamento 0207_0106 (8)
In: Storey 0
Type - PredefinedType: BOLT
Name | Description | NominalDiameter (m)
4 x Collegamento 0207_0106 | M12 | 0.012
2 x Collegamento 0207_0106 | M24 | 0.024
2 x Collegamento 0207_0106 | M12 | 0.0119996

# IfcMechanicalFastener: Collegamento 0207_0107 (24)
In: Storey 0
Type - PredefinedType: BOLT
Name | Description | NominalDiameter (m)
10 x Collegamento 0207_0107 | M12 | 0.0119999
6 x Collegamento 0207_0107 | M12 | 0.012
6 x Collegamento 0207_0107 | M24 | 0.024
2 x Collegamento 0207_0107 | M12 | 0.0120001

# IfcMechanicalFastener: Collegamento 0207_0206 (16)
In: Storey 0
Type - PredefinedType: BOLT
Name | Description | NominalDiameter (m)
8 x Collegamento 0207_0206 | M12 | 0.0119998
4 x Collegamento 0207_0206 | M12 | 0.012
4 x Collegamento 0207_0206 | M24 | 0.024

# IfcMechanicalFastener: Collegamento 0207_0208 (16)
In: Storey 0
Type - PredefinedType: BOLT
Name | Description | NominalDiameter (m)
8 x Collegamento 0207_0208 | M12 | 0.0119998
4 x Collegamento 0207_0208 | M12 | 0.012
4 x Collegamento 0207_0208 | M24 | 0.024

# IfcMechanicalFastener: Collegamento 0208_0108 (24)
In: Storey 0
Type - PredefinedType: BOLT
Name | Description | NominalDiameter (m)
12 x Collegamento 0208_0108 | M12 | 0.0119996
6 x Collegamento 0208_0108 | M12 | 0.012
6 x Collegamento 0208_0108 | M24 | 0.024

# IfcMechanicalFastener: Collegamento 0208_0207 (16)
In: Storey 0
Type - PredefinedType: BOLT
Name | Description | NominalDiameter (m)
8 x Collegamento 0208_0207 | M12 | 0.0119998
4 x Collegamento 0208_0207 | M12 | 0.012
4 x Collegamento 0208_0207 | M24 | 0.024

# IfcMechanicalFastener: Collegamento 0208_0209 (16)
In: Storey 0
Type - PredefinedType: BOLT
Name | Description | NominalDiameter (m)
8 x Collegamento 0208_0209 | M12 | 0.0119998
4 x Collegamento 0208_0209 | M12 | 0.012
4 x Collegamento 0208_0209 | M24 | 0.024

# IfcMechanicalFastener: Collegamento 0209_0109 (24)
In: Storey 0
Type - PredefinedType: BOLT
Name | Description | NominalDiameter (m)
10 x Collegamento 0209_0109 | M12 | 0.0119997
6 x Collegamento 0209_0109 | M12 | 0.012
6 x Collegamento 0209_0109 | M24 | 0.024
2 x Collegamento 0209_0109 | M12 | 0.0119999

# IfcMechanicalFastener: Collegamento 0209_0110 (8)
In: Storey 0
Type - PredefinedType: BOLT
Name | Description | NominalDiameter (m)
2 x Collegamento 0209_0110 | M12 | 0.0119999
2 x Collegamento 0209_0110 | M12 | 0.012
2 x Collegamento 0209_0110 | M24 | 0.024
2 x Collegamento 0209_0110 | M12 | 0.0119997

# IfcMechanicalFastener: Collegamento 0209_0208 (16)
In: Storey 0
Type - PredefinedType: BOLT
Name | Description | NominalDiameter (m)
8 x Collegamento 0209_0208 | M12 | 0.0119998
4 x Collegamento 0209_0208 | M12 | 0.012
4 x Collegamento 0209_0208 | M24 | 0.024

# IfcMechanicalFastener: Collegamento 0209_0210 (16)
In: Storey 0
Type - PredefinedType: BOLT
Name | Description | NominalDiameter (m)
8 x Collegamento 0209_0210 | M12 | 0.0119998
4 x Collegamento 0209_0210 | M12 | 0.012
4 x Collegamento 0209_0210 | M24 | 0.024

# IfcMechanicalFastener: Collegamento 0210_0105 (8)
In: Storey 0
Type - PredefinedType: BOLT
Name | Description | NominalDiameter (m)
4 x Collegamento 0210_0105 | M12 | 0.0119996
2 x Collegamento 0210_0105 | M12 | 0.012
2 x Collegamento 0210_0105 | M24 | 0.024

# IfcMechanicalFastener: Collegamento 0210_0109 (8)
In: Storey 0
Type - PredefinedType: BOLT
Name | Description | NominalDiameter (m)
2 x Collegamento 0210_0109 | M12 | 0.0119997
2 x Collegamento 0210_0109 | M12 | 0.012
2 x Collegamento 0210_0109 | M24 | 0.024
2 x Collegamento 0210_0109 | M12 | 0.0119992

# IfcMechanicalFastener: Collegamento 0210_0110 (24)
In: Storey 0
Type - PredefinedType: BOLT
Name | Description | NominalDiameter (m)
11 x Collegamento 0210_0110 | M12 | 0.0119997
6 x Collegamento 0210_0110 | M12 | 0.012
6 x Collegamento 0210_0110 | M24 | 0.024
Collegamento 0210_0110 | M12 | 0.0119999

# IfcMechanicalFastener: Collegamento 0210_0209 (16)
In: Storey 0
Type - PredefinedType: BOLT
Name | Description | NominalDiameter (m)
8 x Collegamento 0210_0209 | M12 | 0.0119998
4 x Collegamento 0210_0209 | M12 | 0.012
4 x Collegamento 0210_0209 | M24 | 0.024

# IfcPlate: Collegamenti -005_-004 -015_-014 0115_0114 (9)
In: Storey 1
Type - PredefinedType: SHEET

# IfcPlate: Collegamenti 0001_0101 0002_0102 0003_0103 0004_0104 0005_0105 0011_0111 0012_0112 0013_0113 0014_0114 0015_0115 (10)
In: Storey 0
Type - PredefinedType: SHEET

# IfcPlate: Collegamenti 0101_-001 0102_-002 0103_-003 0104_-004 (4)
In: Storey 1
Type - PredefinedType: SHEET

# IfcPlate: Collegamenti 0101_0201 0102_0202 0103_0203 0104_0204 0105_0205 (10)
In: Storey 1
Type - PredefinedType: SHEET

# IfcPlate: Collegamenti 0111_0011 0112_0012 0113_0013 0114_0014 0115_0015 (5)
In: Storey 1
Type - PredefinedType: SHEET

# IfcPlate: Collegamento -001_-002 (3)
In: Storey 1
Type - PredefinedType: SHEET

# IfcPlate: Collegamento -002_-001 (3)
In: Storey 1
Type - PredefinedType: SHEET

# IfcPlate: Collegamento -002_-003 (3)
In: Storey 1
Type - PredefinedType: SHEET

# IfcPlate: Collegamento -003_-002 (3)
In: Storey 1
Type - PredefinedType: SHEET

# IfcPlate: Collegamento -003_-004 (3)
In: Storey 1
Type - PredefinedType: SHEET

# IfcPlate: Collegamento -004_-003 (3)
In: Storey 1
Type - PredefinedType: SHEET

# IfcPlate: Collegamento -004_-005 (3)
In: Storey 1
Type - PredefinedType: SHEET

# IfcPlate: Collegamento -011_-012 (3)
In: Storey 1
Type - PredefinedType: SHEET

# IfcPlate: Collegamento -012_-011 (3)
In: Storey 1
Type - PredefinedType: SHEET

# IfcPlate: Collegamento -012_-013 (3)
In: Storey 1
Type - PredefinedType: SHEET

# IfcPlate: Collegamento -013_-012 (3)
In: Storey 1
Type - PredefinedType: SHEET

# IfcPlate: Collegamento -013_-014 (3)
In: Storey 1
Type - PredefinedType: SHEET

# IfcPlate: Collegamento -014_-013 (3)
In: Storey 1
Type - PredefinedType: SHEET

# IfcPlate: Collegamento -014_-015 (3)
In: Storey 1
Type - PredefinedType: SHEET

# IfcPlate: Collegamento -016_-017 (3)
In: Storey 0
Type - PredefinedType: SHEET

# IfcPlate: Collegamento -017_-016 (3)
In: Storey 0
Type - PredefinedType: SHEET

# IfcPlate: Collegamento -017_-018 (3)
In: Storey 0
Type - PredefinedType: SHEET

# IfcPlate: Collegamento -018_-017 (3)
In: Storey 0
Type - PredefinedType: SHEET

# IfcPlate: Collegamento -018_-019 (3)
In: Storey 0
Type - PredefinedType: SHEET

# IfcPlate: Collegamento -019_-018 (3)
In: Storey 0
Type - PredefinedType: SHEET

# IfcPlate: Collegamento -019_-020 (3)
In: Storey 0
Type - PredefinedType: SHEET

# IfcPlate: Collegamento -020_-019 (3)
In: Storey 0
Type - PredefinedType: SHEET

# IfcPlate: Collegamento -026_-027 (3)
In: Storey 0
Type - PredefinedType: SHEET

# IfcPlate: Collegamento -027_-026 (3)
In: Storey 0
Type - PredefinedType: SHEET

# IfcPlate: Collegamento -027_-028 (3)
In: Storey 0
Type - PredefinedType: SHEET

# IfcPlate: Collegamento -028_-027 (3)
In: Storey 0
Type - PredefinedType: SHEET

# IfcPlate: Collegamento -028_-029 (3)
In: Storey 0
Type - PredefinedType: SHEET

# IfcPlate: Collegamento -029_-028 (3)
In: Storey 0
Type - PredefinedType: SHEET

# IfcPlate: Collegamento -029_-030 (3)
In: Storey 0
Type - PredefinedType: SHEET

# IfcPlate: Collegamento -030_-029 (3)
In: Storey 0
Type - PredefinedType: SHEET

# IfcPlate: Collegamento 0101_0202
In: Storey 1
Type - PredefinedType: SHEET

# IfcPlate: Collegamento 0101_0206
In: Storey 1
Type - PredefinedType: SHEET

# IfcPlate: Collegamento 0102_0201
In: Storey 1
Type - PredefinedType: SHEET

# IfcPlate: Collegamento 0104_0205
In: Storey 1
Type - PredefinedType: SHEET

# IfcPlate: Collegamento 0105_-005
In: Storey 1
Type - PredefinedType: SHEET

# IfcPlate: Collegamento 0105_0204
In: Storey 1
Type - PredefinedType: SHEET

# IfcPlate: Collegamento 0105_0210
In: Storey 1
Type - PredefinedType: SHEET

# IfcPlate: Collegamento 0106_0201
In: Storey 1
Type - PredefinedType: SHEET

# IfcPlate: Collegamento 0106_0206 (5)
In: Storey 1
Type - PredefinedType: SHEET

# IfcPlate: Collegamento 0106_0207
In: Storey 1
Type - PredefinedType: SHEET

# IfcPlate: Collegamento 0107_0206
In: Storey 1
Type - PredefinedType: SHEET

# IfcPlate: Collegamento 0107_0207 (5)
In: Storey 1
Type - PredefinedType: SHEET

# IfcPlate: Collegamento 0108_0208 (5)
In: Storey 1
Type - PredefinedType: SHEET

# IfcPlate: Collegamento 0109_0209 (5)
In: Storey 1
Type - PredefinedType: SHEET

# IfcPlate: Collegamento 0109_0210
In: Storey 1
Type - PredefinedType: SHEET

# IfcPlate: Collegamento 0110_0205
In: Storey 1
Type - PredefinedType: SHEET

# IfcPlate: Collegamento 0110_0209
In: Storey 1
Type - PredefinedType: SHEET

# IfcPlate: Collegamento 0110_0210 (5)
In: Storey 1
Type - PredefinedType: SHEET

# IfcPlate: Collegamento 0111_0112 (3)
In: Storey 1
Type - PredefinedType: SHEET

# IfcPlate: Collegamento 0112_0111 (3)
In: Storey 1
Type - PredefinedType: SHEET

# IfcPlate: Collegamento 0112_0113 (3)
In: Storey 1
Type - PredefinedType: SHEET

# IfcPlate: Collegamento 0113_0112 (3)
In: Storey 1
Type - PredefinedType: SHEET

# IfcPlate: Collegamento 0113_0114 (3)
In: Storey 1
Type - PredefinedType: SHEET

# IfcPlate: Collegamento 0114_0113 (3)
In: Storey 1
Type - PredefinedType: SHEET

# IfcPlate: Collegamento 0114_0115 (3)
In: Storey 1
Type - PredefinedType: SHEET

# IfcPlate: Collegamento 0201_0101
In: Storey 0
Type - PredefinedType: SHEET

# IfcPlate: Collegamento 0201_0102
In: Storey 0
Type - PredefinedType: SHEET

# IfcPlate: Collegamento 0201_0106
In: Storey 0
Type - PredefinedType: SHEET

# IfcPlate: Collegamento 0201_0202 (3)
In: Storey 0
Type - PredefinedType: SHEET

# IfcPlate: Collegamento 0202_0101
In: Storey 0
Type - PredefinedType: SHEET

# IfcPlate: Collegamento 0202_0102
In: Storey 0
Type - PredefinedType: SHEET

# IfcPlate: Collegamento 0202_0201 (3)
In: Storey 0
Type - PredefinedType: SHEET

# IfcPlate: Collegamento 0202_0203 (3)
In: Storey 0
Type - PredefinedType: SHEET

# IfcPlate: Collegamento 0203_0103
In: Storey 0
Type - PredefinedType: SHEET

# IfcPlate: Collegamento 0203_0202 (3)
In: Storey 0
Type - PredefinedType: SHEET

# IfcPlate: Collegamento 0203_0204 (3)
In: Storey 0
Type - PredefinedType: SHEET

# IfcPlate: Collegamento 0204_0104
In: Storey 0
Type - PredefinedType: SHEET

# IfcPlate: Collegamento 0204_0105
In: Storey 0
Type - PredefinedType: SHEET

# IfcPlate: Collegamento 0204_0203 (3)
In: Storey 0
Type - PredefinedType: SHEET

# IfcPlate: Collegamento 0204_0205 (3)
In: Storey 0
Type - PredefinedType: SHEET

# IfcPlate: Collegamento 0205_0104
In: Storey 0
Type - PredefinedType: SHEET

# IfcPlate: Collegamento 0205_0105
In: Storey 0
Type - PredefinedType: SHEET

# IfcPlate: Collegamento 0205_0110
In: Storey 0
Type - PredefinedType: SHEET

# IfcPlate: Collegamento 0205_0204 (3)
In: Storey 0
Type - PredefinedType: SHEET

# IfcPlate: Collegamento 0206_0101
In: Storey 0
Type - PredefinedType: SHEET

# IfcPlate: Collegamento 0206_0106
In: Storey 0
Type - PredefinedType: SHEET

# IfcPlate: Collegamento 0206_0107
In: Storey 0
Type - PredefinedType: SHEET

# IfcPlate: Collegamento 0206_0207 (3)
In: Storey 0
Type - PredefinedType: SHEET

# IfcPlate: Collegamento 0207_0106
In: Storey 0
Type - PredefinedType: SHEET

# IfcPlate: Collegamento 0207_0107
In: Storey 0
Type - PredefinedType: SHEET

# IfcPlate: Collegamento 0207_0206 (3)
In: Storey 0
Type - PredefinedType: SHEET

# IfcPlate: Collegamento 0207_0208 (3)
In: Storey 0
Type - PredefinedType: SHEET

# IfcPlate: Collegamento 0208_0108
In: Storey 0
Type - PredefinedType: SHEET

# IfcPlate: Collegamento 0208_0207 (3)
In: Storey 0
Type - PredefinedType: SHEET

# IfcPlate: Collegamento 0208_0209 (3)
In: Storey 0
Type - PredefinedType: SHEET

# IfcPlate: Collegamento 0209_0109
In: Storey 0
Type - PredefinedType: SHEET

# IfcPlate: Collegamento 0209_0110
In: Storey 0
Type - PredefinedType: SHEET

# IfcPlate: Collegamento 0209_0208 (3)
In: Storey 0
Type - PredefinedType: SHEET

# IfcPlate: Collegamento 0209_0210 (3)
In: Storey 0
Type - PredefinedType: SHEET

# IfcPlate: Collegamento 0210_0105
In: Storey 0
Type - PredefinedType: SHEET

# IfcPlate: Collegamento 0210_0109
In: Storey 0
Type - PredefinedType: SHEET

# IfcPlate: Collegamento 0210_0110
In: Storey 0
Type - PredefinedType: SHEET

# IfcPlate: Collegamento 0210_0209 (3)
In: Storey 0
Type - PredefinedType: SHEET

# IfcReinforcingBar (3)
In: Storey 0
NominalDiameter: 0.012 m; CrossSectionArea: 0.0001131 m2
Name | BarLength (m)
 | 0.328
 | 0.0140465
 | 0.036

# IfcSlab: 1 PANNELLO COPERTURA (12)
In: Storey 0
Type - PredefinedType: FLOOR; Material: Steel
Description: 1 PANNELLO COPERTURA - Altezza solaio 0.000000 - Spessore cappa 0.000000 -
Pset_SlabCommon - LoadBearing: yes
Name | ? (m3)
200 | 0.732877
201 | 0.732877
202 | 0.732877
203 | 0.811767
204 | 0.811767
205 | 0.811767
206 | 0.6174
207 | 0.6174
208 | 0.6174
209 | 1.03243
210 | 1.03243
211 | 1.03243

# IfcSlab: 2 SOLAIO INTERMEDIO (12)
In: Storey 1
Type - PredefinedType: FLOOR; Material: Steel
Description: 2 SOLAIO INTERMEDIO - Altezza solaio 0.000000 - Spessore cappa 0.000000 -
Pset_SlabCommon - LoadBearing: yes
Name | ? (m3)
100 | 1.13567
101 | 1.13567
102 | 1.13567
103 | 0.679141
104 | 0.67914
105 | 0.67914
106 | 0.892943
107 | 0.892943
108 | 0.892944
109 | 0.806164
110 | 0.806164
111 | 0.806164

# IfcWall (10)
Material: Steel
Pset_WallCommon - LoadBearing: yes
Name | In
104 | Storey 0
103 | Storey 0
102 | Storey 0
101 | Storey 0
106 | Storey 0
105 | Storey 1
204 | Storey 1
203 | Storey 1
202 | Storey 1
201 | Storey 1

# IfcReinforcingBarType, no part of this type: type
PredefinedType: MAIN; NominalDiameter: 0.012 m; CrossSectionArea: 0.0001131 m2; BarLength: 0.328 m; Material: Steel

# IfcReinforcingBarType, no part of this type: type
PredefinedType: MAIN; NominalDiameter: 0.012 m; CrossSectionArea: 0.0001131 m2; BarLength: 0.0140465 m; Material: Steel

# IfcReinforcingBarType, no part of this type: type
PredefinedType: MAIN; NominalDiameter: 0.012 m; CrossSectionArea: 0.0001131 m2; BarLength: 0.036 m; Material: Steel

# Material: Acciaio
Acciaio - Mass Density: 7850; Poisson Ratio: 0.3; Shear Modulus: 8000000000; Thermal Expansion Coefficient: 0.00001; Young Modulus: 20999999488

# Material: Acciaio
Acciaio - Mass Density: 7850; Poisson Ratio: 0.3; Shear Modulus: 8000000000; Thermal Expansion Coefficient: 0.00001; Young Modulus: 20999999488

# Material: Acciaio
Acciaio - Mass Density: 7850; Poisson Ratio: 0.3; Shear Modulus: 8000000000; Thermal Expansion Coefficient: 0.00001; Young Modulus: 20999999488

# Material: Acciaio
Acciaio - Mass Density: 7850; Poisson Ratio: 0.3; Shear Modulus: 8000000000; Thermal Expansion Coefficient: 0.00001; Young Modulus: 20999999488

# Material: Acciaio
Acciaio - Mass Density: 7850; Poisson Ratio: 0.3; Shear Modulus: 8000000000; Thermal Expansion Coefficient: 0.00001; Young Modulus: 20999999488

# Material: Acciaio
Acciaio - Mass Density: 7850; Poisson Ratio: 0.3; Shear Modulus: 8000000000; Thermal Expansion Coefficient: 0.00001; Young Modulus: 20999999488

# Material: Acciaio
Acciaio - Mass Density: 7850; Poisson Ratio: 0.3; Shear Modulus: 8000000000; Thermal Expansion Coefficient: 0.00001; Young Modulus: 20999999488

# Material: Acciaio
Acciaio - Mass Density: 7850; Poisson Ratio: 0.3; Shear Modulus: 8000000000; Thermal Expansion Coefficient: 0.00001; Young Modulus: 20999999488

# Material: Acciaio
Acciaio - Mass Density: 7850; Poisson Ratio: 0.3; Shear Modulus: 8000000000; Thermal Expansion Coefficient: 0.00001; Young Modulus: 20999999488

# Material: Acciaio
Acciaio - Mass Density: 7850; Poisson Ratio: 0.3; Shear Modulus: 8000000000; Thermal Expansion Coefficient: 0.00001; Young Modulus: 20999999488

# Material: Acciaio
Acciaio - Mass Density: 7850; Poisson Ratio: 0.3; Shear Modulus: 8000000000; Thermal Expansion Coefficient: 0.00001; Young Modulus: 20999999488

# Material: Acciaio
Acciaio - Mass Density: 7850; Poisson Ratio: 0.3; Shear Modulus: 8000000000; Thermal Expansion Coefficient: 0.00001; Young Modulus: 20999999488

# Material: Acciaio
Acciaio - Mass Density: 7850; Poisson Ratio: 0.3; Shear Modulus: 8000000000; Thermal Expansion Coefficient: 0.00001; Young Modulus: 20999999488

# Material: Acciaio
Acciaio - Mass Density: 7850; Poisson Ratio: 0.3; Shear Modulus: 8000000000; Thermal Expansion Coefficient: 0.00001; Young Modulus: 20999999488

# Material: Acciaio
Acciaio - Mass Density: 7850; Poisson Ratio: 0.3; Shear Modulus: 8000000000; Thermal Expansion Coefficient: 0.00001; Young Modulus: 20999999488

# Material: Acciaio
Acciaio - Mass Density: 7850; Poisson Ratio: 0.3; Shear Modulus: 8000000000; Thermal Expansion Coefficient: 0.00001; Young Modulus: 20999999488

# Material: Acciaio
Acciaio - Mass Density: 7850; Poisson Ratio: 0.3; Shear Modulus: 8000000000; Thermal Expansion Coefficient: 0.00001; Young Modulus: 20999999488

# Material: Acciaio
Acciaio - Mass Density: 7850; Poisson Ratio: 0.3; Shear Modulus: 8000000000; Thermal Expansion Coefficient: 0.00001; Young Modulus: 20999999488

# Material: Acciaio
Acciaio - Mass Density: 7850; Poisson Ratio: 0.3; Shear Modulus: 8000000000; Thermal Expansion Coefficient: 0.00001; Young Modulus: 20999999488

# Material: Acciaio
Acciaio - Mass Density: 7850; Poisson Ratio: 0.3; Shear Modulus: 8000000000; Thermal Expansion Coefficient: 0.00001; Young Modulus: 20999999488

# Material: Acciaio
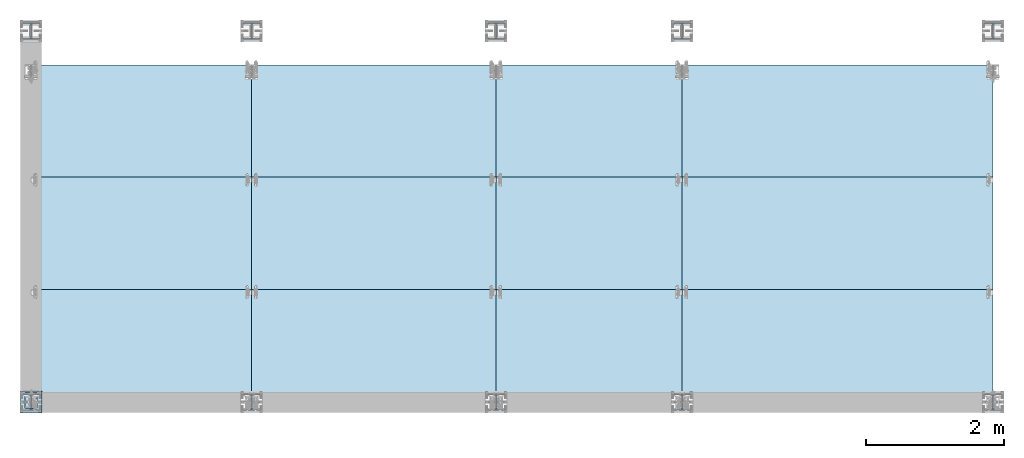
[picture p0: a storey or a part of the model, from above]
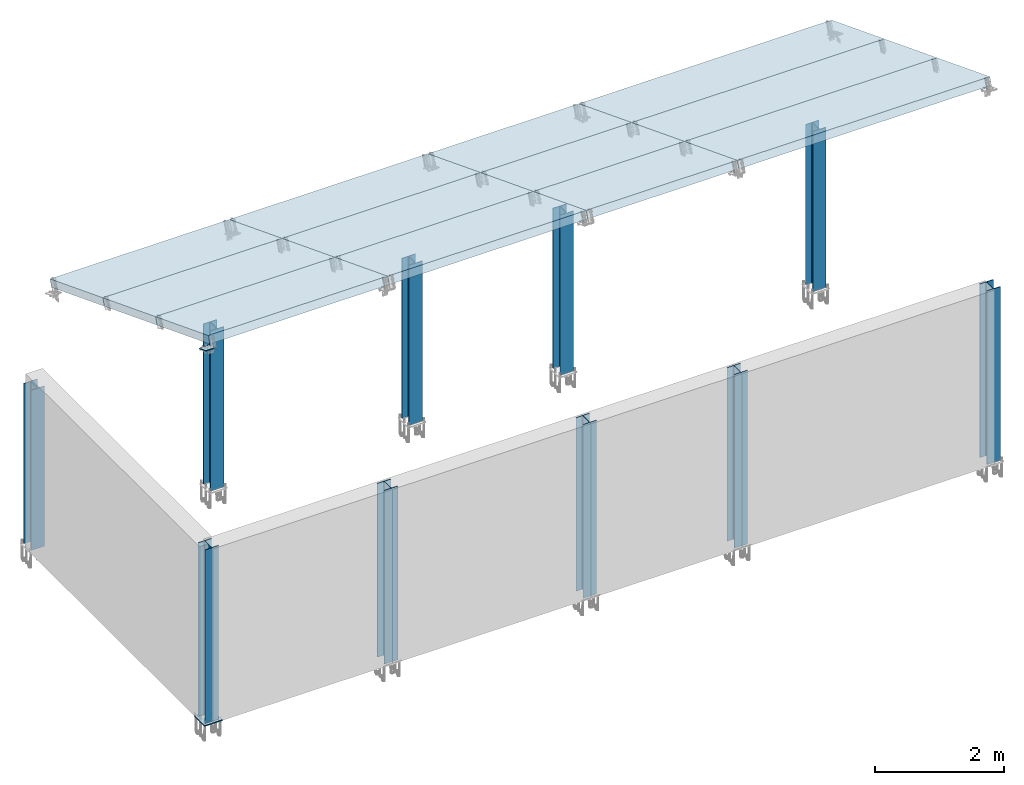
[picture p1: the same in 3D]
Properties of the parts of a building model (IFC4), part 2 of 2

Acciaio - Mass Density: 7850; Poisson Ratio: 0.3; Shear Modulus: 8000000000; Thermal Expansion Coefficient: 0.00001; Young Modulus: 20999999488

# Material: Acciaio
Acciaio - Mass Density: 7850; Poisson Ratio: 0.3; Shear Modulus: 8000000000; Thermal Expansion Coefficient: 0.00001; Young Modulus: 20999999488

# Material: Acciaio
Acciaio - Mass Density: 7850; Poisson Ratio: 0.3; Shear Modulus: 8000000000; Thermal Expansion Coefficient: 0.00001; Young Modulus: 20999999488

# Material: Acciaio
Acciaio - Mass Density: 7850; Poisson Ratio: 0.3; Shear Modulus: 8000000000; Thermal Expansion Coefficient: 0.00001; Young Modulus: 20999999488

# Material: Acciaio
Acciaio - Mass Density: 7850; Poisson Ratio: 0.3; Shear Modulus: 8000000000; Thermal Expansion Coefficient: 0.00001; Young Modulus: 20999999488

# Material: Acciaio
Acciaio - Mass Density: 7850; Poisson Ratio: 0.3; Shear Modulus: 8000000000; Thermal Expansion Coefficient: 0.00001; Young Modulus: 20999999488

# Material: Acciaio
Acciaio - Mass Density: 7850; Poisson Ratio: 0.3; Shear Modulus: 8000000000; Thermal Expansion Coefficient: 0.00001; Young Modulus: 20999999488

# Material: Acciaio
Acciaio - Mass Density: 7850; Poisson Ratio: 0.3; Shear Modulus: 8000000000; Thermal Expansion Coefficient: 0.00001; Young Modulus: 20999999488

# Material: Acciaio
Acciaio - Mass Density: 7850; Poisson Ratio: 0.3; Shear Modulus: 8000000000; Thermal Expansion Coefficient: 0.00001; Young Modulus: 20999999488

# Material: Acciaio
Acciaio - Mass Density: 7850; Poisson Ratio: 0.3; Shear Modulus: 8000000000; Thermal Expansion Coefficient: 0.00001; Young Modulus: 20999999488

# Material: Acciaio
Acciaio - Mass Density: 7850; Poisson Ratio: 0.3; Shear Modulus: 8000000000; Thermal Expansion Coefficient: 0.00001; Young Modulus: 20999999488

# Material: Acciaio
Acciaio - Mass Density: 7850; Poisson Ratio: 0.3; Shear Modulus: 8000000000; Thermal Expansion Coefficient: 0.00001; Young Modulus: 20999999488

# Material: Acciaio
Acciaio - Mass Density: 7850; Poisson Ratio: 0.3; Shear Modulus: 8000000000; Thermal Expansion Coefficient: 0.00001; Young Modulus: 20999999488

# Material: Acciaio
Acciaio - Mass Density: 7850; Poisson Ratio: 0.3; Shear Modulus: 8000000000; Thermal Expansion Coefficient: 0.00001; Young Modulus: 20999999488

# Material: Acciaio
Acciaio - Mass Density: 7850; Poisson Ratio: 0.3; Shear Modulus: 8000000000; Thermal Expansion Coefficient: 0.00001; Young Modulus: 20999999488

# Material: Acciaio
Acciaio - Mass Density: 7850; Poisson Ratio: 0.3; Shear Modulus: 8000000000; Thermal Expansion Coefficient: 0.00001; Young Modulus: 20999999488

# Material: Acciaio
Acciaio - Mass Density: 7850; Poisson Ratio: 0.3; Shear Modulus: 8000000000; Thermal Expansion Coefficient: 0.00001; Young Modulus: 20999999488

# Material: Acciaio
Acciaio - Mass Density: 7850; Poisson Ratio: 0.3; Shear Modulus: 8000000000; Thermal Expansion Coefficient: 0.00001; Young Modulus: 20999999488

# Material: Acciaio
Acciaio - Mass Density: 7850; Poisson Ratio: 0.3; Shear Modulus: 8000000000; Thermal Expansion Coefficient: 0.00001; Young Modulus: 20999999488

# Material: Acciaio
Acciaio - Mass Density: 7850; Poisson Ratio: 0.3; Shear Modulus: 8000000000; Thermal Expansion Coefficient: 0.00001; Young Modulus: 20999999488

# Material: Acciaio
Acciaio - Mass Density: 7850; Poisson Ratio: 0.3; Shear Modulus: 8000000000; Thermal Expansion Coefficient: 0.00001; Young Modulus: 20999999488

# Material: Acciaio
Acciaio - Mass Density: 7850; Poisson Ratio: 0.3; Shear Modulus: 8000000000; Thermal Expansion Coefficient: 0.00001; Young Modulus: 20999999488

# Material: Acciaio
Acciaio - Mass Density: 7850; Poisson Ratio: 0.3; Shear Modulus: 8000000000; Thermal Expansion Coefficient: 0.00001; Young Modulus: 20999999488

# Material: Acciaio
Acciaio - Mass Density: 7850; Poisson Ratio: 0.3; Shear Modulus: 8000000000; Thermal Expansion Coefficient: 0.00001; Young Modulus: 20999999488

# Material: Acciaio
Acciaio - Mass Density: 7850; Poisson Ratio: 0.3; Shear Modulus: 8000000000; Thermal Expansion Coefficient: 0.00001; Young Modulus: 20999999488

# Material: Acciaio
Acciaio - Mass Density: 7850; Poisson Ratio: 0.3; Shear Modulus: 8000000000; Thermal Expansion Coefficient: 0.00001; Young Modulus: 20999999488

# Material: Acciaio
Acciaio - Mass Density: 7850; Poisson Ratio: 0.3; Shear Modulus: 8000000000; Thermal Expansion Coefficient: 0.00001; Young Modulus: 20999999488

# Material: Acciaio
Acciaio - Mass Density: 7850; Poisson Ratio: 0.3; Shear Modulus: 8000000000; Thermal Expansion Coefficient: 0.00001; Young Modulus: 20999999488

# Material: Acciaio
Acciaio - Mass Density: 7850; Poisson Ratio: 0.3; Shear Modulus: 8000000000; Thermal Expansion Coefficient: 0.00001; Young Modulus: 20999999488

# Material: Acciaio
Acciaio - Mass Density: 7850; Poisson Ratio: 0.3; Shear Modulus: 8000000000; Thermal Expansion Coefficient: 0.00001; Young Modulus: 20999999488

# Material: Acciaio
Acciaio - Mass Density: 7850; Poisson Ratio: 0.3; Shear Modulus: 8000000000; Thermal Expansion Coefficient: 0.00001; Young Modulus: 20999999488

# Material: Acciaio
Acciaio - Mass Density: 7850; Poisson Ratio: 0.3; Shear Modulus: 8000000000; Thermal Expansion Coefficient: 0.00001; Young Modulus: 20999999488

# Material: Acciaio
Acciaio - Mass Density: 7850; Poisson Ratio: 0.3; Shear Modulus: 8000000000; Thermal Expansion Coefficient: 0.00001; Young Modulus: 20999999488

# Material: Acciaio
Acciaio - Mass Density: 7850; Poisson Ratio: 0.3; Shear Modulus: 8000000000; Thermal Expansion Coefficient: 0.00001; Young Modulus: 20999999488

# Material: Acciaio
Acciaio - Mass Density: 7850; Poisson Ratio: 0.3; Shear Modulus: 8000000000; Thermal Expansion Coefficient: 0.00001; Young Modulus: 20999999488

# Material: Acciaio
Acciaio - Mass Density: 7850; Poisson Ratio: 0.3; Shear Modulus: 8000000000; Thermal Expansion Coefficient: 0.00001; Young Modulus: 20999999488

# Material: Acciaio
Acciaio - Mass Density: 7850; Poisson Ratio: 0.3; Shear Modulus: 8000000000; Thermal Expansion Coefficient: 0.00001; Young Modulus: 20999999488

# Material: Acciaio
Acciaio - Mass Density: 7850; Poisson Ratio: 0.3; Shear Modulus: 8000000000; Thermal Expansion Coefficient: 0.00001; Young Modulus: 20999999488

# Material: Acciaio
Acciaio - Mass Density: 7850; Poisson Ratio: 0.3; Shear Modulus: 8000000000; Thermal Expansion Coefficient: 0.00001; Young Modulus: 20999999488

# Material: Acciaio
Acciaio - Mass Density: 7850; Poisson Ratio: 0.3; Shear Modulus: 8000000000; Thermal Expansion Coefficient: 0.00001; Young Modulus: 20999999488

# Material: Acciaio
Acciaio - Mass Density: 7850; Poisson Ratio: 0.3; Shear Modulus: 8000000000; Thermal Expansion Coefficient: 0.00001; Young Modulus: 20999999488

# Material: Acciaio
Acciaio - Mass Density: 7850; Poisson Ratio: 0.3; Shear Modulus: 8000000000; Thermal Expansion Coefficient: 0.00001; Young Modulus: 20999999488

# Material: Acciaio
Acciaio - Mass Density: 7850; Poisson Ratio: 0.3; Shear Modulus: 8000000000; Thermal Expansion Coefficient: 0.00001; Young Modulus: 20999999488

# Material: Acciaio
Acciaio - Mass Density: 7850; Poisson Ratio: 0.3; Shear Modulus: 8000000000; Thermal Expansion Coefficient: 0.00001; Young Modulus: 20999999488

# Material: Acciaio
Acciaio - Mass Density: 7850; Poisson Ratio: 0.3; Shear Modulus: 8000000000; Thermal Expansion Coefficient: 0.00001; Young Modulus: 20999999488

# Material: Acciaio
Acciaio - Mass Density: 7850; Poisson Ratio: 0.3; Shear Modulus: 8000000000; Thermal Expansion Coefficient: 0.00001; Young Modulus: 20999999488

# Material: Acciaio
Acciaio - Mass Density: 7850; Poisson Ratio: 0.3; Shear Modulus: 8000000000; Thermal Expansion Coefficient: 0.00001; Young Modulus: 20999999488

# Material: Acciaio
Acciaio - Mass Density: 7850; Poisson Ratio: 0.3; Shear Modulus: 8000000000; Thermal Expansion Coefficient: 0.00001; Young Modulus: 20999999488

# Material: Acciaio
Acciaio - Mass Density: 7850; Poisson Ratio: 0.3; Shear Modulus: 8000000000; Thermal Expansion Coefficient: 0.00001; Young Modulus: 20999999488

# Material: Acciaio
Acciaio - Mass Density: 7850; Poisson Ratio: 0.3; Shear Modulus: 8000000000; Thermal Expansion Coefficient: 0.00001; Young Modulus: 20999999488

# Material: Acciaio
Acciaio - Mass Density: 7850; Poisson Ratio: 0.3; Shear Modulus: 8000000000; Thermal Expansion Coefficient: 0.00001; Young Modulus: 20999999488

# Material: Acciaio
Acciaio - Mass Density: 7850; Poisson Ratio: 0.3; Shear Modulus: 8000000000; Thermal Expansion Coefficient: 0.00001; Young Modulus: 20999999488

# Material: Acciaio
Acciaio - Mass Density: 7850; Poisson Ratio: 0.3; Shear Modulus: 8000000000; Thermal Expansion Coefficient: 0.00001; Young Modulus: 20999999488

# Material: Acciaio
Acciaio - Mass Density: 7850; Poisson Ratio: 0.3; Shear Modulus: 8000000000; Thermal Expansion Coefficient: 0.00001; Young Modulus: 20999999488

# Material: Acciaio
Acciaio - Mass Density: 7850; Poisson Ratio: 0.3; Shear Modulus: 8000000000; Thermal Expansion Coefficient: 0.00001; Young Modulus: 20999999488

# Material: Acciaio
Acciaio - Mass Density: 7850; Poisson Ratio: 0.3; Shear Modulus: 8000000000; Thermal Expansion Coefficient: 0.00001; Young Modulus: 20999999488

# Material: Acciaio
Acciaio - Mass Density: 7850; Poisson Ratio: 0.3; Shear Modulus: 8000000000; Thermal Expansion Coefficient: 0.00001; Young Modulus: 20999999488

# Material: Acciaio
Acciaio - Mass Density: 7850; Poisson Ratio: 0.3; Shear Modulus: 8000000000; Thermal Expansion Coefficient: 0.00001; Young Modulus: 20999999488

# Material: Acciaio
Acciaio - Mass Density: 7850; Poisson Ratio: 0.3; Shear Modulus: 8000000000; Thermal Expansion Coefficient: 0.00001; Young Modulus: 20999999488

# Material: Acciaio
Acciaio - Mass Density: 7850; Poisson Ratio: 0.3; Shear Modulus: 8000000000; Thermal Expansion Coefficient: 0.00001; Young Modulus: 20999999488

# Material: Acciaio
Acciaio - Mass Density: 7850; Poisson Ratio: 0.3; Shear Modulus: 8000000000; Thermal Expansion Coefficient: 0.00001; Young Modulus: 20999999488

# Material: Acciaio
Acciaio - Mass Density: 7850; Poisson Ratio: 0.3; Shear Modulus: 8000000000; Thermal Expansion Coefficient: 0.00001; Young Modulus: 20999999488

# Material: Acciaio
Acciaio - Mass Density: 7850; Poisson Ratio: 0.3; Shear Modulus: 8000000000; Thermal Expansion Coefficient: 0.00001; Young Modulus: 20999999488

# Material: Acciaio
Acciaio - Mass Density: 7850; Poisson Ratio: 0.3; Shear Modulus: 8000000000; Thermal Expansion Coefficient: 0.00001; Young Modulus: 20999999488

# Material: Acciaio
Acciaio - Mass Density: 7850; Poisson Ratio: 0.3; Shear Modulus: 8000000000; Thermal Expansion Coefficient: 0.00001; Young Modulus: 20999999488

# Material: Acciaio
Acciaio - Mass Density: 7850; Poisson Ratio: 0.3; Shear Modulus: 8000000000; Thermal Expansion Coefficient: 0.00001; Young Modulus: 20999999488

# Material: Acciaio
Acciaio - Mass Density: 7850; Poisson Ratio: 0.3; Shear Modulus: 8000000000; Thermal Expansion Coefficient: 0.00001; Young Modulus: 20999999488

# Material: Acciaio
Acciaio - Mass Density: 7850; Poisson Ratio: 0.3; Shear Modulus: 8000000000; Thermal Expansion Coefficient: 0.00001; Young Modulus: 20999999488

# Material: Acciaio
Acciaio - Mass Density: 7850; Poisson Ratio: 0.3; Shear Modulus: 8000000000; Thermal Expansion Coefficient: 0.00001; Young Modulus: 20999999488

# Material: Acciaio
Acciaio - Mass Density: 7850; Poisson Ratio: 0.3; Shear Modulus: 8000000000; Thermal Expansion Coefficient: 0.00001; Young Modulus: 20999999488

# Material: Acciaio
Acciaio - Mass Density: 7850; Poisson Ratio: 0.3; Shear Modulus: 8000000000; Thermal Expansion Coefficient: 0.00001; Young Modulus: 20999999488

# Material: Acciaio
Acciaio - Mass Density: 7850; Poisson Ratio: 0.3; Shear Modulus: 8000000000; Thermal Expansion Coefficient: 0.00001; Young Modulus: 20999999488

# Material: Acciaio
Acciaio - Mass Density: 7850; Poisson Ratio: 0.3; Shear Modulus: 8000000000; Thermal Expansion Coefficient: 0.00001; Young Modulus: 20999999488

# Material: Acciaio
Acciaio - Mass Density: 7850; Poisson Ratio: 0.3; Shear Modulus: 8000000000; Thermal Expansion Coefficient: 0.00001; Young Modulus: 20999999488

# Material: Acciaio
Acciaio - Mass Density: 7850; Poisson Ratio: 0.3; Shear Modulus: 8000000000; Thermal Expansion Coefficient: 0.00001; Young Modulus: 20999999488

# Material: Acciaio
Acciaio - Mass Density: 7850; Poisson Ratio: 0.3; Shear Modulus: 8000000000; Thermal Expansion Coefficient: 0.00001; Young Modulus: 20999999488

# Material: Acciaio
Acciaio - Mass Density: 7850; Poisson Ratio: 0.3; Shear Modulus: 8000000000; Thermal Expansion Coefficient: 0.00001; Young Modulus: 20999999488

# Material: Acciaio controventi
Acciaio controventi - Mass Density: 7850; Poisson Ratio: 0.3; Shear Modulus: 8000000000; Thermal Expansion Coefficient: 0.00001; Young Modulus: 10499999744

# Material: Acciaio controventi
Acciaio controventi - Mass Density: 7850; Poisson Ratio: 0.3; Shear Modulus: 8000000000; Thermal Expansion Coefficient: 0.00001; Young Modulus: 10499999744

# Material: Acciaio controventi
Acciaio controventi - Mass Density: 7850; Poisson Ratio: 0.3; Shear Modulus: 8000000000; Thermal Expansion Coefficient: 0.00001; Young Modulus: 10499999744

# Material: Acciaio controventi
Acciaio controventi - Mass Density: 7850; Poisson Ratio: 0.3; Shear Modulus: 8000000000; Thermal Expansion Coefficient: 0.00001; Young Modulus: 10499999744

# Material: Acciaio controventi
Acciaio controventi - Mass Density: 7850; Poisson Ratio: 0.3; Shear Modulus: 8000000000; Thermal Expansion Coefficient: 0.00001; Young Modulus: 10499999744

# Material: Acciaio controventi
Acciaio controventi - Mass Density: 7850; Poisson Ratio: 0.3; Shear Modulus: 8000000000; Thermal Expansion Coefficient: 0.00001; Young Modulus: 10499999744

# Material: Acciaio controventi
Acciaio controventi - Mass Density: 7850; Poisson Ratio: 0.3; Shear Modulus: 8000000000; Thermal Expansion Coefficient: 0.00001; Young Modulus: 10499999744

# Material: Acciaio controventi
Acciaio controventi - Mass Density: 7850; Poisson Ratio: 0.3; Shear Modulus: 8000000000; Thermal Expansion Coefficient: 0.00001; Young Modulus: 10499999744

# Material: Acciaio controventi
Acciaio controventi - Mass Density: 7850; Poisson Ratio: 0.3; Shear Modulus: 8000000000; Thermal Expansion Coefficient: 0.00001; Young Modulus: 10499999744

# Material: Acciaio controventi
Acciaio controventi - Mass Density: 7850; Poisson Ratio: 0.3; Shear Modulus: 8000000000; Thermal Expansion Coefficient: 0.00001; Young Modulus: 10499999744

# Material: Acciaio controventi
Acciaio controventi - Mass Density: 7850; Poisson Ratio: 0.3; Shear Modulus: 8000000000; Thermal Expansion Coefficient: 0.00001; Young Modulus: 10499999744

# Material: Acciaio controventi
Acciaio controventi - Mass Density: 7850; Poisson Ratio: 0.3; Shear Modulus: 8000000000; Thermal Expansion Coefficient: 0.00001; Young Modulus: 10499999744
